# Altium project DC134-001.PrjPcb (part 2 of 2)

## Sheet DC134_USB.SchDoc
size 431 x 279 mm; Date: Not shown in title block; ApprovedBy: Not shown in title block; CheckedBy: Not shown in title block; Author: Not shown in title block; CompanyName: Not shown in title block; Engineer: Not shown in title block; Organization: Not shown in title block; Address1: Not shown in title block; Address2: Not shown in title block; Address3: Not shown in title block; Address4: Not shown in title block; DocumentNumber: 5; Revision: Use project parameter SCH_Rev; SheetNumber: 5; SheetTotal: 9; PageSetup: Record=PageOptions¦CenterHorizontal=True¦CenterVertical=True¦PrintScale=1.00¦XCorrection=1.00¦YCorrection=1.00¦PrintKind=0¦BorderSize=5000000¦LeftOffset=0¦BottomOffset=0¦Orientation=2¦PaperLength=1000¦PaperWidth=1000¦Scale=100¦PaperSource=15¦PrintQuality=600¦MediaType=1¦DitherType=10¦PaperKind=Letter¦PrintScaleMode=1

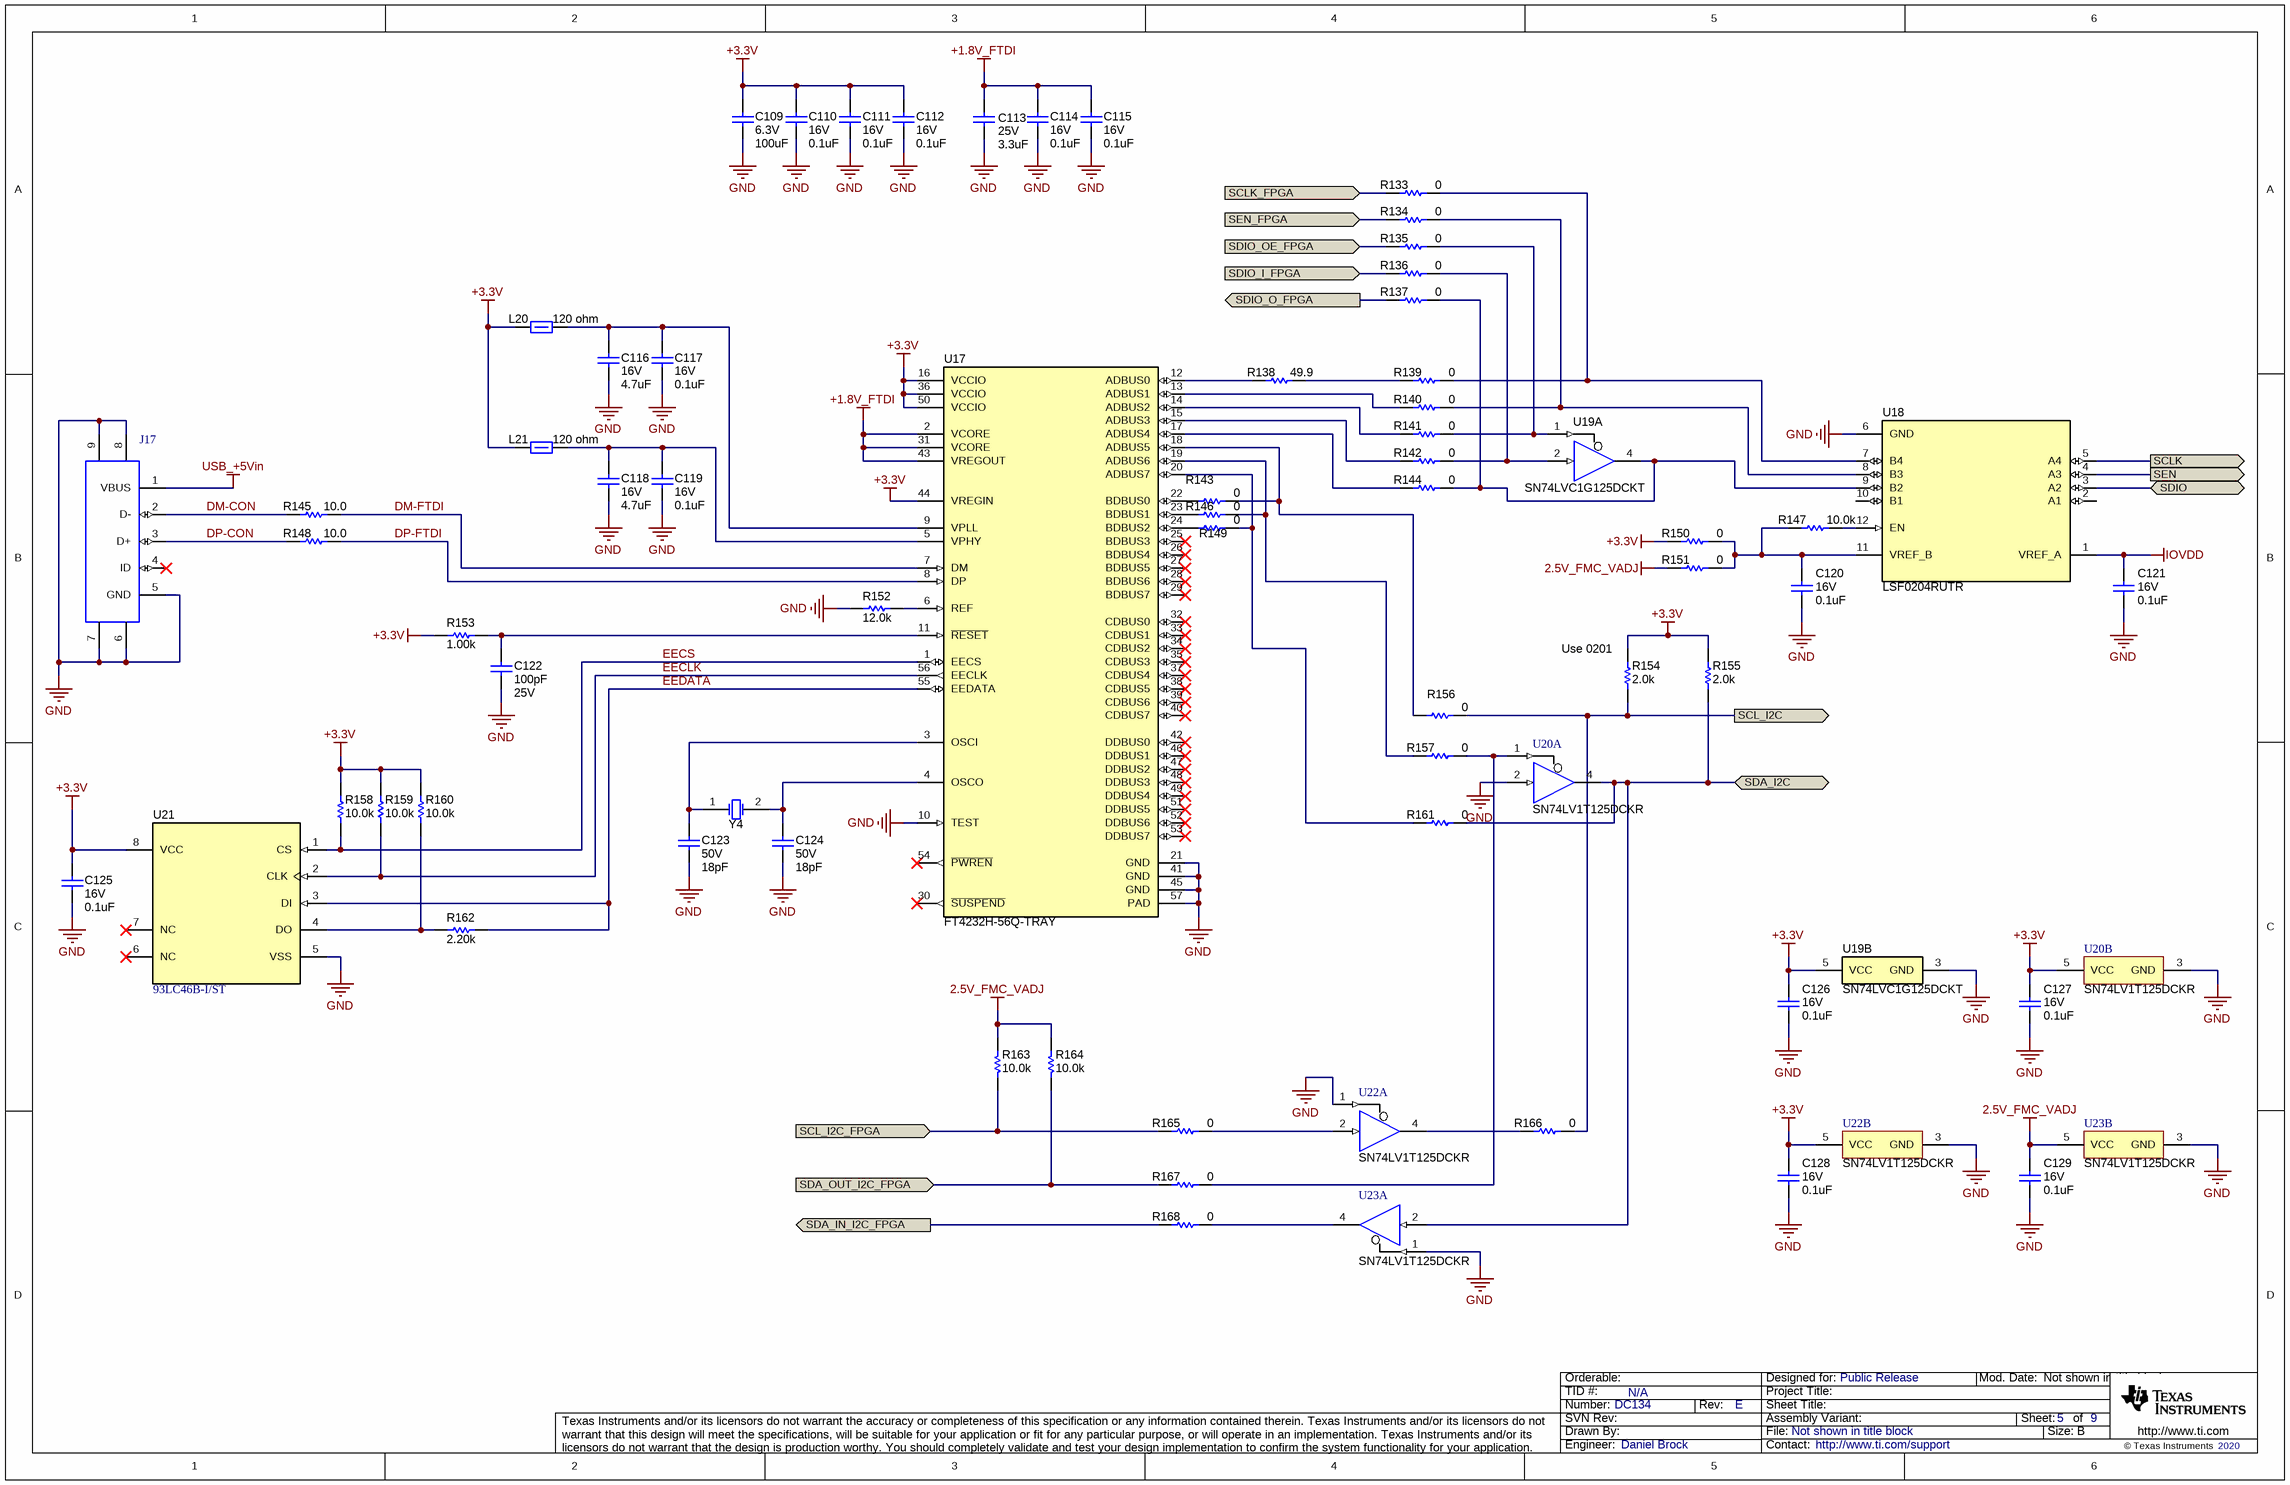
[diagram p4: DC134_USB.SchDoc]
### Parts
C109  VDC_V: 6.3V  ValueDisplayed: 100uF  [1206_190]  (hidden comment: C3216X5R0J107M160AB)
C110  VDC_V: 16V  ValueDisplayed: 0.1uF  [0201L]  (hidden comment: GRM033Z71C104KE14D)
C111  VDC_V: 16V  ValueDisplayed: 0.1uF  [0201L]  (hidden comment: GRM033Z71C104KE14D)
C112  VDC_V: 16V  ValueDisplayed: 0.1uF  [0201L]  (hidden comment: GRM033Z71C104KE14D)
C113  Value2: 25V  ValueDisplayed: 3.3uF  [0603]  (hidden comment: C1608X5R1E335K080AC)
C114  VDC_V: 16V  ValueDisplayed: 0.1uF  [0201L]  (hidden comment: GRM033Z71C104KE14D)
C115  VDC_V: 16V  ValueDisplayed: 0.1uF  [0201L]  (hidden comment: GRM033Z71C104KE14D)
C116  VDC_V: 16V  ValueDisplayed: 4.7uF  [0603]  (hidden comment: GRM188Z71C475KE21D)
C117  VDC_V: 16V  ValueDisplayed: 0.1uF  [0201L]  (hidden comment: GRM033Z71C104KE14D)
C118  VDC_V: 16V  ValueDisplayed: 4.7uF  [0603]  (hidden comment: GRM188Z71C475KE21D)
C119  VDC_V: 16V  ValueDisplayed: 0.1uF  [0201L]  (hidden comment: GRM033Z71C104KE14D)
C120  VDC_V: 16V  ValueDisplayed: 0.1uF  [0201L]  (hidden comment: GRM033Z71C104KE14D)
C121  VDC_V: 16V  ValueDisplayed: 0.1uF  [0201L]  (hidden comment: GRM033Z71C104KE14D)
C122  ValueDisplayed: 100pF  VDC_V: 25V  [0201L]  (hidden comment: CC0201JRNPO8BN101)
C123  VDC_V: 50V  ValueDisplayed: 18pF  [0402L]  (hidden comment: C1005C0G1H180J050BA)
C124  VDC_V: 50V  ValueDisplayed: 18pF  [0402L]  (hidden comment: C1005C0G1H180J050BA)
C125  VDC_V: 16V  ValueDisplayed: 0.1uF  [0201L]  (hidden comment: GRM033Z71C104KE14D)
C126  VDC_V: 16V  ValueDisplayed: 0.1uF  [0201L]  (hidden comment: GRM033Z71C104KE14D)
C127  VDC_V: 16V  ValueDisplayed: 0.1uF  [0201L]  (hidden comment: GRM033Z71C104KE14D)
C128  VDC_V: 16V  ValueDisplayed: 0.1uF  [0201L]  (hidden comment: GRM033Z71C104KE14D)
C129  VDC_V: 16V  ValueDisplayed: 0.1uF  [0201L]  (hidden comment: GRM033Z71C104KE14D)
J17  1734035-2  [CONN_USB-Mini-B-1734035-2]  (value not drawn)
L20  ValueDisplayed: 120 ohm  [0402]  (hidden comment: 74279271)
L21  ValueDisplayed: 120 ohm  [0402]  (hidden comment: 74279271)
R133  ValueDisplayed: 0  [0201L]  (hidden comment: CRCW02010000Z0ED)
R134  ValueDisplayed: 0  [0201L]  (hidden comment: CRCW02010000Z0ED)
R135  ValueDisplayed: 0  [0201L]  (hidden comment: CRCW02010000Z0ED)
R136  ValueDisplayed: 0  [0201L]  (hidden comment: CRCW02010000Z0ED)
R137  ValueDisplayed: 0  [0201L]  (hidden comment: CRCW02010000Z0ED)
R138  ValueDisplayed: 49.9  [0201L]  (hidden comment: RC0201FR-7D49R9L)
R139  ValueDisplayed: 0  [0201L]  (hidden comment: CRCW02010000Z0ED)
R140  ValueDisplayed: 0  [0201L]  (hidden comment: CRCW02010000Z0ED)
R141  ValueDisplayed: 0  [0201L]  (hidden comment: CRCW02010000Z0ED)
R142  ValueDisplayed: 0  [0201L]  (hidden comment: CRCW02010000Z0ED)
R143  ValueDisplayed: 0  [0201L]  (hidden comment: CRCW02010000Z0ED)
R144  ValueDisplayed: 0  [0201L]  (hidden comment: CRCW02010000Z0ED)
R145  ValueDisplayed: 10.0  [0402]  (hidden comment: RK73H1ETTP10R0F)
R146  ValueDisplayed: 0  [0201L]  (hidden comment: CRCW02010000Z0ED)
R147  ValueDisplayed: 10.0k  [0201L]  (hidden comment: RC0201FS-7D10KL)
R148  ValueDisplayed: 10.0  [0402]  (hidden comment: RK73H1ETTP10R0F)
R149  ValueDisplayed: 0  [0201L]  (hidden comment: CRCW02010000Z0ED)
R150  ValueDisplayed: 0  [0201L]  (hidden comment: CRCW02010000Z0ED)
R151  ValueDisplayed: 0  [0201L]  (hidden comment: CRCW02010000Z0ED)
R152  ValueDisplayed: 12.0k  [0201L]  (hidden comment: RC0201FR-7D12KL)
R153  ValueDisplayed: 1.00k  [0201L]  (hidden comment: RC0201FS-7D1KL)
R154  ValueDisplayed: 2.0k  [0402]  (hidden comment: CRCW04022K00JNED)
R155  ValueDisplayed: 2.0k  [0402]  (hidden comment: CRCW04022K00JNED)
R156  ValueDisplayed: 0  [0201L]  (hidden comment: CRCW02010000Z0ED)
R157  ValueDisplayed: 0  [0201L]  (hidden comment: CRCW02010000Z0ED)
R158  ValueDisplayed: 10.0k  [0201L]  (hidden comment: RC0201FR-7D10KL)
R159  ValueDisplayed: 10.0k  [0201L]  (hidden comment: RC0201FR-7D10KL)
R160  ValueDisplayed: 10.0k  [0201L]  (hidden comment: RC0201FR-7D10KL)
R161  ValueDisplayed: 0  [0201L]  (hidden comment: CRCW02010000Z0ED)
R162  ValueDisplayed: 2.20k  [0201L]  (hidden comment: RC0201FR-7D2K2L)
R163  ValueDisplayed: 10.0k  [0201L]  (hidden comment: RC0201FR-7D10KL)
R164  ValueDisplayed: 10.0k  [0201L]  (hidden comment: RC0201FR-7D10KL)
R165  ValueDisplayed: 0  [0201L]  (hidden comment: CRCW02010000Z0ED)
R166  ValueDisplayed: 0  [0201L]  (hidden comment: CRCW02010000Z0ED)
R167  ValueDisplayed: 0  [0201L]  (hidden comment: CRCW02010000Z0ED)
R168  ValueDisplayed: 0  [0201L]  (hidden comment: CRCW02010000Z0ED)
U17  FT4232H-56Q-TRAY  [VQFN-56]
U18  LSF0204RUTR  [RUT0012A]
U19  SN74LVC1G125DCKT  [DCK0005A_N]  (parts A,B of 2)
U20  SN74LV1T125DCKR  [DCK0005A_N]  (parts A,B of 2)
U21  93LC46B-I/ST  [TSSOP-8]
U22  SN74LV1T125DCKR  [DCK0005A_N]  (parts A,B of 2)
U23  SN74LV1T125DCKR  [DCK0005A_N]  (parts A,B of 2)
Y4  ABM3-12.000MHZ-D2Y-T  [XTAL_ABM3]  (value not drawn)

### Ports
SCL_I2C (out), SCL_I2C_FPGA (in), SCLK (out), SCLK_FPGA (in), SDA_I2C (bidir), SDA_IN_I2C_FPGA (out), SDA_OUT_I2C_FPGA (in), SDIO (bidir), SDIO_I_FPGA (in), SDIO_O_FPGA (out), SDIO_OE_FPGA (in), SEN (out), SEN_FPGA (in)

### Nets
2.5V_FMC_VADJ: C129.1 R151.1 R163.1 R164.1 U23.5(VCC)
+1.8V_FTDI: C113.1 C114.2 C115.2 U17.2(VCORE) U17.31(VCORE) U17.43(VREGOUT)
+3.3V: C109.1 C110.2 C111.2 C112.2 C125.2 C126.1 C127.1 C128.1 L20.1 L21.1 R150.1 R153.1 R154.2 R155.2 R158.2 R159.2 R160.2 U17.16(VCCIO) U17.36(VCCIO) U17.44(VREGIN) U17.50(VCCIO) U19.5(VCC) U20.5(VCC) U21.8(VCC) U22.5(VCC)
GND: C109.2 C110.1 C111.1 C112.1 C113.2 C114.1 C115.1 C116.2 C117.1 C118.2 C119.1 C120.2 C121.2 C122.2 C123.2 C124.2 C125.1 C126.2 C127.2 C128.2 C129.2 J17.5(GND) J17.6 J17.7 J17.8 J17.9 R152.1 U17.10(TEST) U17.21(GND) U17.41(GND) U17.45(GND) U17.57(PAD) U18.6(GND) U19.3(GND) U20.2(A) U20.3(GND) U21.5(VSS) U22.1(~{OE}) U22.3(GND) U23.1(~{OE}) U23.3(GND)
IOVDD: C121.1 U18.1(VREF_A)
USB_+5Vin: J17.1(VBUS)
DM-CON: J17.2(D-) R145.1
DM-FTDI: R145.2 U17.7(DM)
DP-CON: J17.3(D+) R148.1
DP-FTDI: R148.2 U17.8(DP)
EECLK: R159.1 U17.56(EECLK) U21.2(CLK)
EECS: R158.1 U17.1(EECS) U21.1(CS)
EEDATA: R162.2 U17.55(EEDATA) U21.3(DI)
SCL_I2C: R154.1 R156.2 R166.2 ; port SCL_I2C
SCL_I2C_FPGA: R163.2 R165.1 ; port SCL_I2C_FPGA
SCLK: U18.5(A4) ; port SCLK
SCLK_FPGA: R133.1 ; port SCLK_FPGA
SDA_I2C: R155.1 R161.2 U20.4(Y) U23.2(A) ; port SDA_I2C
SDA_IN_I2C_FPGA: R168.1 ; port SDA_IN_I2C_FPGA
SDA_OUT_I2C_FPGA: R164.2 R167.1 ; port SDA_OUT_I2C_FPGA
SDIO: U18.3(A2) ; port SDIO
SDIO_I_FPGA: R136.1 ; port SDIO_I_FPGA
SDIO_O_FPGA: R137.1 ; port SDIO_O_FPGA
SDIO_OE_FPGA: R135.1 ; port SDIO_OE_FPGA
SEN: U18.4(A3) ; port SEN
SEN_FPGA: R134.1 ; port SEN_FPGA
NetC116_1: C116.1 C117.2 L20.2 U17.9(VPLL)
NetC118_1: C118.1 C119.2 L21.2 U17.5(VPHY)
NetC120_1: C120.1 R147.2 R150.2 R151.2 U18.11(VREF_B)
NetC122_1: C122.1 R153.2 U17.11(~{RESET})
NetC123_1: C123.1 U17.3(OSCI) Y4.1(OSC1)
NetC124_1: C124.1 U17.4(OSCO) Y4.2(OSC2)
NetR133_2: R133.2 R139.2 U18.7(B4)
NetR134_2: R134.2 R140.2 U18.8(B3)
NetR135_2: R135.2 R141.2 U19.1(~{OE})
NetR136_2: R136.2 R142.2 U19.2(A)
NetR137_2: R137.2 R144.2 U18.9(B2) U19.4(Y)
NetR138_1: R138.1 U17.12(ADBUS0)
NetR138_2: R138.2 R139.1
NetR140_1: R140.1 U17.13(ADBUS1)
NetR141_1: R141.1 U17.14(ADBUS2)
NetR142_1: R142.1 U17.15(ADBUS3)
NetR143_1: R143.1 U17.22(BDBUS0)
NetR143_2: R143.2 R156.1 U17.18(ADBUS5)
NetR144_1: R144.1 U17.17(ADBUS4)
NetR146_1: R146.1 U17.23(BDBUS1)
NetR146_2: R146.2 R157.1 U17.19(ADBUS6)
NetR147_1: R147.1 U18.12(EN)
NetR149_1: R149.1 U17.24(BDBUS2)
NetR149_2: R149.2 R161.1 U17.20(ADBUS7)
NetR152_2: R152.2 U17.6(REF)
NetR157_2: R157.2 R167.2 U20.1(~{OE})
NetR160_1: R160.1 R162.1 U21.4(DO)
NetR165_2: R165.2 U22.2(A)
NetR166_1: R166.1 U22.4(Y)
NetR168_2: R168.2 U23.4(Y)

Not connected (* = marked no-connect by the designer): J17 4(ID)*; U17 25(BDBUS3)* 26(BDBUS4)* 27(BDBUS5)* 28(BDBUS6)* 29(BDBUS7)* 30(~{SUSPEND})* 32(CDBUS0)* 33(CDBUS1)* 34(CDBUS2)* 35(CDBUS3)* 37(CDBUS4)* 38(CDBUS5)* 39(CDBUS6)* 40(CDBUS7)* 42(DDBUS0)* 46(DDBUS1)* 47(DDBUS2)* 48(DDBUS3)* 49(DDBUS4)* 51(DDBUS5)* 52(DDBUS6)* 53(DDBUS7)* 54(~{PWREN})*; U18 2(A1) 10(B1); U21 6(NC)* 7(NC)*

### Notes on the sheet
- (near R154) Use 0201

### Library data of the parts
C109 = CMP-0064957-2: CAP, CERM, 100 uF, 6.3 V,+/- 20%, X5R, 1206; Manufacturer: TDK; TaMin_C: -55°C; Polarized: N; SizeAreaWB_mm2: 10.92; Value1: Unknown; U/M: EA; Value: 100uF; TaMax_C: 85°C; SizeZ_mm: 1.9; SizeX_mm: 3.2; SizeY_mm: 1.6; Cap_Case: 1206; SizeArea_mm2: 5.12; Cap_F: 100µF; AEC Category: Q200
C110-C112 C114 C115 C117 C119 C125 = CMP-0064970-1: CAP, CERM, 0.1 uF, 16 V,+/- 10%, X7R, 0201; Manufacturer: MuRata; TaMin_C: -55°C; Polarized: N; SizeAreaWB_mm2: 2.08; Value1: Unknown; U/M: EA; Value: 0.1uF; TaMax_C: 125°C; SizeZ_mm: 0.26; SizeX_mm: 0.6; SizeY_mm: 0.3; Cap_Case: 0201; SizeArea_mm2: 0.18; Cap_F: 100nF; AEC Category: Q200
C113 = CMP-0007008-5: CAP, CERM, 3.3 uF, 25 V, +/- 10%, X5R, 0603; Manufacturer: TDK; TaMin_C: -55°C; Polarized: N; SizeAreaWB_mm2: 4.68; Value1: Unknown; U/M: EA; Value: 3.3uF; TaMax_C: 85°C; SizeZ_mm: 1; SizeX_mm: 1.6; SizeY_mm: 0.8; SizeArea_mm2: 1.28; Cap_F: 3.3µF; AEC Category: Q200
C116 C118 = CMP-0064936-4: CAP, CERM, 4.7 uF, 16 V,+/- 10%, X7R, 0603; Manufacturer: MuRata; TaMin_C: -55°C; Polarized: N; SizeAreaWB_mm2: 4.68; Value1: Unknown; U/M: EA; Value: 4.7uF; TaMax_C: 125°C; SizeZ_mm: 1; SizeX_mm: 1.6; SizeY_mm: 0.8; SizeArea_mm2: 1.28; Cap_F: 4.7µF; AEC Category: Q200
C120 C121 C126-C129 = CMP-0064970-1: CAP, CERM, 0.1 uF, 16 V,+/- 10%, X7R, 0201; Manufacturer: MuRata; TaMin_C: -55°C; Polarized: N; SizeAreaWB_mm2: 2.08; Value1: Unknown; U/M: EA; Value: 0.1uF; TaMax_C: 125°C; SizeZ_mm: 0.26; SizeX_mm: 0.6; SizeY_mm: 0.3; Cap_Case: 0201; SizeArea_mm2: 0.18; CompType: Capacitor; Cap_F: 100nF; AEC Category: Q200
C122 = CMP-0085847-1: CAP, CERM, 100 pF, 25 V,+/- 5%, C0G/NP0, 0201; Manufacturer: Yageo; Polarized: N; Cap_Case: 0201; SizeX_mm: 0.6; TaMin_C: -55°C; AEC Category: Q200; SizeY_mm: 0.3; SizeZ_mm: 0.26; Value: 100pF; U/M: EA; SizeAreaWB_mm2: 2.08; TaMax_C: 125°C; SizeArea_mm2: 0.18
C123 C124 = CMP-0006247-2: CAP, CERM, 18 pF, 50 V, +/- 5%, C0G/NP0, 0402; Manufacturer: TDK; TaMin_C: -55°C; Polarized: N; SizeAreaWB_mm2: 3; Value1: Unknown; U/M: EA; Value: 18pF; TaMax_C: 125°C; SizeZ_mm: 0.6; SizeX_mm: 1; SizeY_mm: 0.5; Cap_Case: 0402; AEC Category: Q200
J17 = CMP-0054920-3: Connector, Receptacle, Mini-USB Type B, R/A, Top Mount SMT; Manufacturer: TE Connectivity; Green_Lifecycle: Active; Gender: Female; Green_REACh: Incomplete; CompType: USB
L20 L21 = CMP-0003214-1: Ferrite Bead, 120 ohm @ 100 MHz, 0.5 A, 0402; Manufacturer: Wurth Elektronik; Ztyp@1GHz_Ohm: 175.42; ZTyp@100MHz_Ohm: 120; SizeAreaWB_mm2: 3; DCR_ohm: 2d; Value1: 0.2 ohm; Value: 120 ohm; Imax_A: 5dA; SizeZ_mm: 0.6; SizeX_mm: 1; SizeY_mm: 0.5; Value2: 0.5A
R133-R137 R139-R144 R146 R149-R151 R156 R157 R161 R165-R168 = CMP-0027008-4: RES, 0, 5%, 0.05 W, 0201; Manufacturer: Vishay-Dale; Power_W: 50mW; TempCo: ppm/C; Value_Code: 0000; Value: 0; EIA_Code: E24; SizeX_mm: 0.6; SizeY_mm: 0.3; SizeZ_mm: 0.26; Value2: 0.05W; SizeArea_mm2: 0.18; CompType: Resistor; AEC Qualified: N; AEC Category: Q200
R138 = CMP-0028028-1: RES, 49.9, 1%, 0.05 W, 0201; Manufacturer: Yageo America; Power_W: 50mW; TempCo: 200 ppm/C; Value_Code: 49R9; U/M: EA; Value: 49.9; EIA_Code: E96; SizeX_mm: 0.6; SizeY_mm: 0.3; SizeZ_mm: 0.26; Value2: 0.05W; SizeArea_mm2: 0.18; AEC Qualified: N; VDC_V: 25V; AEC Category: Q200
R145 R148 = CMP-0026749-1: RES, 10.0, 1%, 0.063 W, 0402; Manufacturer: KOA Speer; Power_W: 63mW; TempCo: 100 ppm/C; Value_Code: 10R0; U/M: EA; Value: 10.0; EIA_Code: E96; Res_ohm: 10; SizeX_mm: 1; SizeY_mm: 0.5; SizeZ_mm: 0.6; Value2: 0.063W; AEC Qualified: N; VDC_V: 50V; AEC Category: Q200
R147 = CMP-0028071-1: RES, 10.0 k, 1%, 0.05 W, 0201; Manufacturer: Yageo America; Power_W: 50mW; TempCo: 200 ppm/C; Value_Code: 10k0; U/M: EA; Value: 10.0k; EIA_Code: E96; Res_ohm: 10k; SizeX_mm: 0.6; SizeY_mm: 0.3; SizeZ_mm: 0.26; Value2: 0.05W; SizeArea_mm2: 0.18; CompType: Resistor; AEC Qualified: N; VDC_V: 25V; AEC Category: Q200
R152 = CMP-0027954-1: RES, 12.0 k, 1%, 0.05 W, 0201; Manufacturer: Yageo America; Power_W: 50mW; TempCo: 200 ppm/C; Value_Code: 12k0; U/M: EA; Value: 12.0k; Res_ohm: 12k; SizeX_mm: 0.6; SizeY_mm: 0.3; SizeZ_mm: 0.26; Value2: 0.05W; SizeArea_mm2: 0.18; CompType: Resistor; AEC Qualified: N; VDC_V: 25V; AEC Category: Q200
R153 = CMP-0028084-1: RES, 1.00 k, 1%, 0.05 W, 0201; Manufacturer: Yageo America; Power_W: 50mW; TempCo: 200 ppm/C; Value_Code: 1k00; U/M: EA; Value: 1.00k; EIA_Code: E96; Res_ohm: 1k; SizeX_mm: 0.6; SizeY_mm: 0.3; SizeZ_mm: 0.26; Value2: 0.05W; SizeArea_mm2: 0.18; AEC Qualified: N; VDC_V: 25V; AEC Category: Q200
R154 R155 = CMP-0026889-5: RES, 2.0 k, 5%, 0.063 W, AEC-Q200 Grade 0, 0402; Manufacturer: Vishay-Dale; Power_W: 63mW; TempCo: 200 ppm/C; Value_Code: 2k00; Value: 2.0k; EIA_Code: E24; Res_ohm: 2k; SizeX_mm: 1; SizeY_mm: 0.5; SizeZ_mm: 0.6; Value2: 0.063W; AEC Qualified: Y; VDC_V: 50V; AEC Category: Q200; AEC Grade: 0
R158-R160 R163 = CMP-0027945-1: RES, 10.0 k, 1%, 0.05 W, 0201; Manufacturer: Yageo America; Power_W: 50mW; TempCo: 200 ppm/C; Value_Code: 10k0; U/M: EA; Value: 10.0k; EIA_Code: E96; Res_ohm: 10k; SizeX_mm: 0.6; SizeY_mm: 0.3; SizeZ_mm: 0.26; Value2: 0.05W; SizeArea_mm2: 0.18; AEC Qualified: N; VDC_V: 25V; AEC Category: Q200
R162 = CMP-0027995-1: RES, 2.20 k, 1%, 0.05 W, 0201; Manufacturer: Yageo America; Power_W: 50mW; TempCo: 200 ppm/C; Value_Code: 2k20; U/M: EA; Value: 2.20k; Res_ohm: 2.2k; SizeX_mm: 0.6; SizeY_mm: 0.3; SizeZ_mm: 0.26; Value2: 0.05W; SizeArea_mm2: 0.18; AEC Qualified: N; VDC_V: 25V; AEC Category: Q200
R164 = CMP-0027945-1: RES, 10.0 k, 1%, 0.05 W, 0201; Manufacturer: Yageo America; Power_W: 50mW; TempCo: 200 ppm/C; Value_Code: 10k0; U/M: EA; Value: 10.0k; EIA_Code: E96; Res_ohm: 10k; SizeX_mm: 0.6; SizeY_mm: 0.3; SizeZ_mm: 0.26; Value2: 0.05W; SizeArea_mm2: 0.18; CompType: Resistor; AEC Qualified: N; VDC_V: 25V; AEC Category: Q200
U17 = CMP-0081661-1: Future Technology Devices International Ltd FT4232H Quad High Speed USB to Multipurpose UART/MPSSE IC, VQFN-56; Manufacturer: FTDI; SizeZ_mm: 1; SizeX_mm: 8; SizeArea_mm2: 64; SizeAreaWB_mm2: 100
U18 = CMP-0066443-2: 4-Bit Bidirectional Multi-Voltage Level Translator for Open-Drain & Push- Pull, RUT0012A (UQFN-12); Manufacturer: Texas Instruments; SizeZ_mm: 0.55; SizeX_mm: 1.7; SizeY_mm: 2.0; SizeArea_mm2: 3.4; CompType: IC; U/M: EA; SizeAreaWB_mm2: 8.1
U19 = CMP-0051305-3: Single Bus Buffer Gate With 3-State Outputs, DCK0005A, SMALL T&R; Manufacturer: Texas Instruments; Output Type: CMOS; tpd @ Nom Voltage(Max)(ns): 9,5.5,4.5,4; VCC(Max)(V): 5.5; 3-State Output: Yes; VCC(Min)(V): 1.65; Input Type: CMOS/TTL; Rating: Catalog; Sub-Family: Non-Inverting Buffer/Driver; F @ Nom Voltage(Max)(Mhz): 150; Bits(#): 1; Schmitt Trigger: No; Voltage(Nom)(V): 1.8,2.5,3.3,5; Output Drive (IOL/IOH)(Max)(mA): 32/-32; Technology Family: LVC; ICC @ Nom Voltage(Max)(mA): 0.01; Logic: True; AEC Category: Q200; AEC Qualified: N; CompType: IC; SizeAreaWB_mm2: 9.3; SizeArea_mm2: 4.2; SizeX_mm: 2.1; SizeY_mm: 2.0; SizeZ_mm: 1.1
U20 U22 U23 = CMP-0051325-2: Single Power Supply, Single BUFFER GATE w/ 3-State Output (active low enable), DCK0005A, LARGE T&R; Manufacturer: Texas Instruments; tpd @ Nom Voltage(Max)(ns): 14.5,9.5,8.0,6.5; Output Drive (IOL/IOH)(Max)(mA): 8/-8; Voltage(Nom)(V): 1.8,2.5,3.3,5.5; Bits(#): 1; Rating: Catalog; Output Type: CMOS; Technology Family: LV1T; 3-State Output: Yes; Sub-Family: Non-Inverting Buffer/Driver; Logic: True; Input Type: TTL; Schmitt Trigger: No; VCC(Min)(V): 1.6; Special Features: 1.8V to 3.3V Up Translation,3.3V to 1.8V Down Translation,5V Input Tolerant; VCC(Max)(V): 5.5; ICC @ Nom Voltage(Max)(mA): 0.01; F @ Nom Voltage(Max)(Mhz): 50; AEC Category: Q200; AEC Qualified: N; CompType: IC; SizeAreaWB_mm2: 9.3; SizeArea_mm2: 4.2; SizeX_mm: 2.1; SizeY_mm: 2.0; SizeZ_mm: 1.1
U21 = CMP-0081524-1: 1K Microwire Compatible Serial EEPROM, TSSOP-8; Manufacturer: Microchip; SizeArea_mm2: 19.2; SizeAreaWB_mm2: 42; SizeY_mm: 3; SizeZ_mm: 1.2; SizeX_mm: 6.4
Y4 = CMP-0004616-3: Crystal, 12 MHz, 18 pF, SMD; Manufacturer: Abracon Corporation; TaMin_C: -40°C; Frequency Stability: +/-30ppm; Frequency_Fixed: 12MHz; TaMax_C: 85°C

## Sheet DC134_Power.SchDoc: Power-Supply_Buffer
size 431 x 279 mm; Date: Not shown in title block; ApprovedBy: Not shown in title block; CheckedBy: Not shown in title block; Author: Not shown in title block; CompanyName: Not shown in title block; DrawnBy: Daniel Brock; Engineer: Not shown in title block; Organization: Not shown in title block; Address1: Not shown in title block; Address2: Not shown in title block; Address3: Not shown in title block; Address4: Not shown in title block; DocumentNumber: 6; Revision: Use project parameter SCH_Rev; SheetNumber: 6; SheetTotal: 9; PageSetup: Record=PageOptions¦CenterHorizontal=True¦CenterVertical=True¦PrintScale=1.00¦XCorrection=1.00¦YCorrection=1.00¦PrintKind=0¦BorderSize=5000000¦LeftOffset=0¦BottomOffset=0¦Orientation=2¦PaperLength=1000¦PaperWidth=1000¦Scale=100¦PaperSource=15¦PrintQuality=600¦MediaType=1¦DitherType=10¦PaperKind=Letter¦PrintScaleMode=1

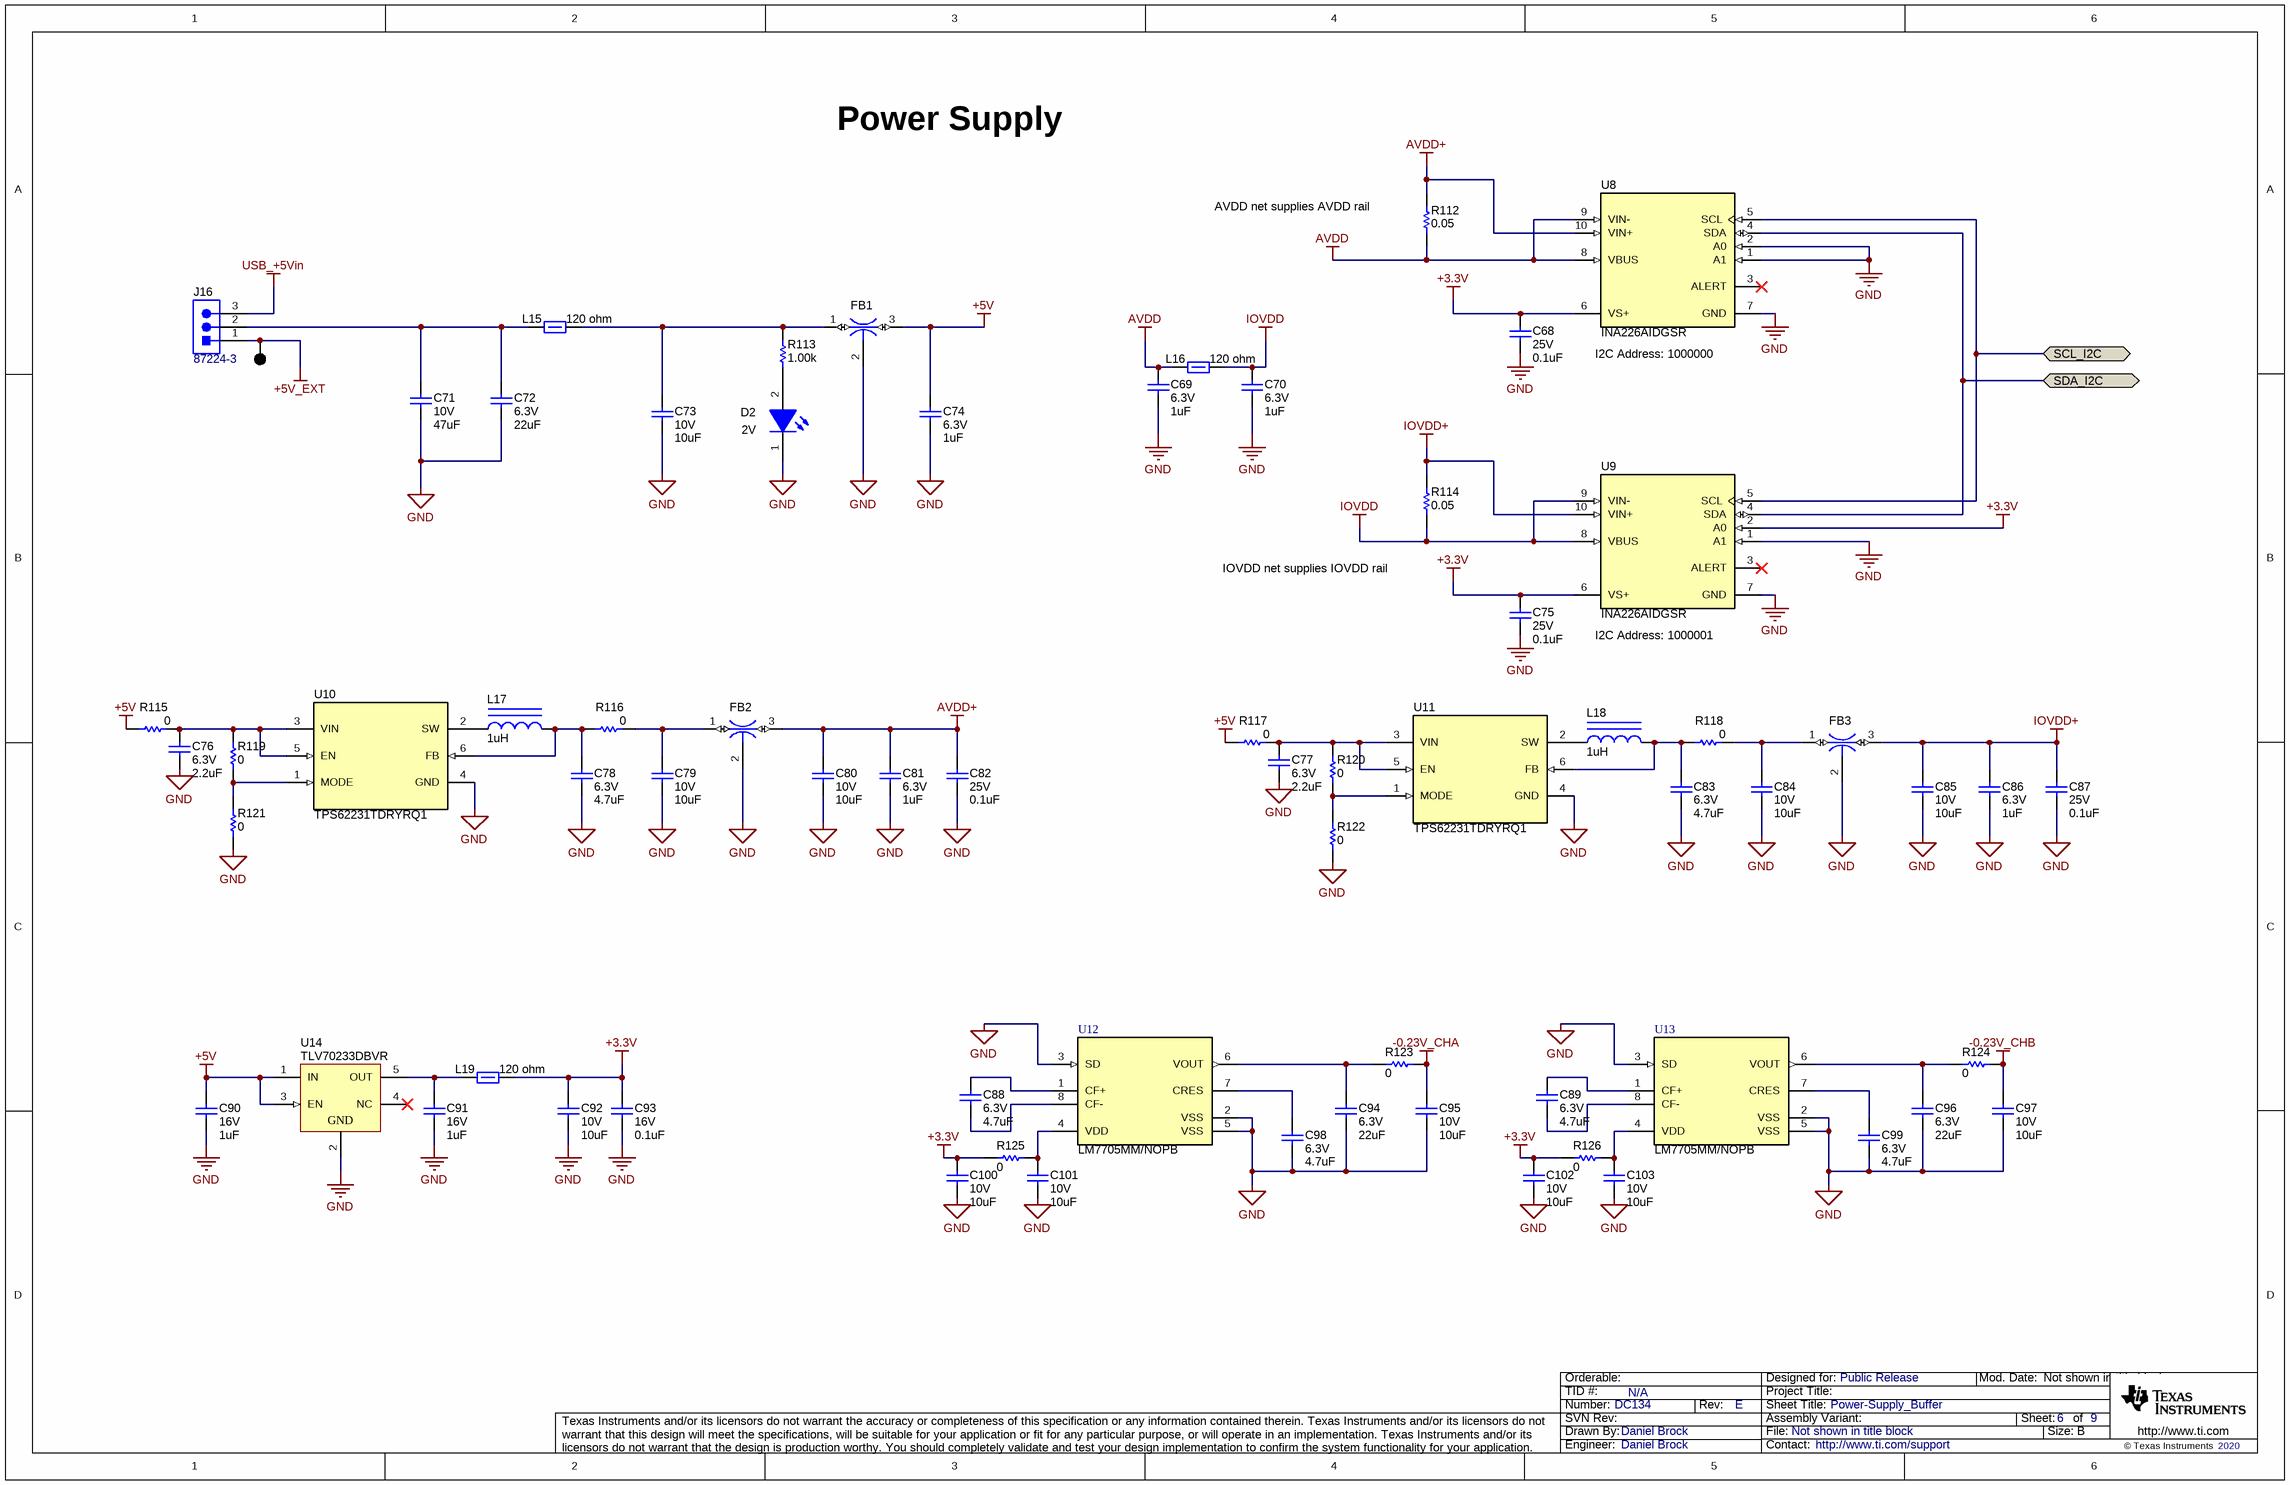
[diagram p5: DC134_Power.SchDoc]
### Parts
+1  5011  [Keystone5011]  (value not drawn)
C68  VDC_V: 25V  ValueDisplayed: 0.1uF  [0402]  (hidden comment: GRM155R61E104KA87D)
C69  VDC_V: 6.3V  ValueDisplayed: 1uF  [0402]  (hidden comment: GRM152R60J105ME15D)
C70  VDC_V: 6.3V  ValueDisplayed: 1uF  [0402]  (hidden comment: GRM152R60J105ME15D)
C71  VDC_V: 10V  ValueDisplayed: 47uF  [1210_270]  (hidden comment: GRM32ER61A476KE20L)
C72  VDC_V: 6.3V  ValueDisplayed: 22uF  [0805_HV]  (hidden comment: JMK212BJ226MG-T)
C73  VDC_V: 10V  ValueDisplayed: 10uF  [0603]  (hidden comment: GRM188R61A106ME69D)
C74  VDC_V: 6.3V  ValueDisplayed: 1uF  [0402]  (hidden comment: GRM152R60J105ME15D)
C75  VDC_V: 25V  ValueDisplayed: 0.1uF  [0402]  (hidden comment: GRM155R61E104KA87D)
C76  VDC_V: 6.3V  ValueDisplayed: 2.2uF  [0402]  (hidden comment: GRM155R60J225ME15D)
C77  VDC_V: 6.3V  ValueDisplayed: 2.2uF  [0402]  (hidden comment: GRM155R60J225ME15D)
C78  VDC_V: 6.3V  ValueDisplayed: 4.7uF  [0603]  (hidden comment: C0603C475K9PACTU)
C79  VDC_V: 10V  ValueDisplayed: 10uF  [0603]  (hidden comment: GRM188R61A106ME69D)
C80  VDC_V: 10V  ValueDisplayed: 10uF  [0603]  (hidden comment: GRM188R61A106ME69D)
C81  VDC_V: 6.3V  ValueDisplayed: 1uF  [0402]  (hidden comment: GRM152R60J105ME15D)
C82  VDC_V: 25V  ValueDisplayed: 0.1uF  [0201_033]  (hidden comment: GRM033R61E104KE14J)
C83  VDC_V: 6.3V  ValueDisplayed: 4.7uF  [0603]  (hidden comment: C0603C475K9PACTU)
C84  VDC_V: 10V  ValueDisplayed: 10uF  [0603]  (hidden comment: GRM188R61A106ME69D)
C85  VDC_V: 10V  ValueDisplayed: 10uF  [0603]  (hidden comment: GRM188R61A106ME69D)
C86  VDC_V: 6.3V  ValueDisplayed: 1uF  [0402]  (hidden comment: GRM152R60J105ME15D)
C87  VDC_V: 25V  ValueDisplayed: 0.1uF  [0201_033]  (hidden comment: GRM033R61E104KE14J)
C88  VDC_V: 6.3V  ValueDisplayed: 4.7uF  [0603]  (hidden comment: C0603C475K9PACTU)
C89  VDC_V: 6.3V  ValueDisplayed: 4.7uF  [0603]  (hidden comment: C0603C475K9PACTU)
C90  VDC_V: 16V  ValueDisplayed: 1uF  [0603]  (hidden comment: 885012206052)
C91  VDC_V: 16V  ValueDisplayed: 1uF  [0603]  (hidden comment: 885012206052)
C92  VDC_V: 10V  ValueDisplayed: 10uF  [0805_HV]  (hidden comment: 885012207026)
C93  VDC_V: 16V  ValueDisplayed: 0.1uF  [0201L]  (hidden comment: GRM033Z71C104KE14D)
C94  VDC_V: 6.3V  ValueDisplayed: 22uF  [0805_HV]  (hidden comment: JMK212BJ226MG-T)
C95  VDC_V: 10V  ValueDisplayed: 10uF  [0805_HV]  (hidden comment: 885012207026)
C96  VDC_V: 6.3V  ValueDisplayed: 22uF  [0805_HV]  (hidden comment: JMK212BJ226MG-T)
C97  VDC_V: 10V  ValueDisplayed: 10uF  [0805_HV]  (hidden comment: 885012207026)
C98  VDC_V: 6.3V  ValueDisplayed: 4.7uF  [0603]  (hidden comment: C0603C475K9PACTU)
C99  VDC_V: 6.3V  ValueDisplayed: 4.7uF  [0603]  (hidden comment: C0603C475K9PACTU)
C100  VDC_V: 10V  ValueDisplayed: 10uF  [0805_HV]  (hidden comment: 885012207026)
C101  VDC_V: 10V  ValueDisplayed: 10uF  [0805_HV]  (hidden comment: 885012207026)
C102  VDC_V: 10V  ValueDisplayed: 10uF  [0805_HV]  (hidden comment: 885012207026)
C103  VDC_V: 10V  ValueDisplayed: 10uF  [0805_HV]  (hidden comment: 885012207026)
D2  Value2: 2V  [LTST-C150_1206_Green]  (hidden comment: LTST-C150KGKT)
FB1  NFM31PC276B0J3L  [Murata_NFM31P]  (value not drawn)
FB2  NFM31PC276B0J3L  [Murata_NFM31P]  (value not drawn)
FB3  NFM31PC276B0J3L  [Murata_NFM31P]  (value not drawn)
J16  87224-3  [TE_87224-3]
L15  ValueDisplayed: 120 ohm  [0402]  (hidden comment: 74279271)
L16  ValueDisplayed: 120 ohm  [0402]  (hidden comment: 74279271)
L17  ValueDisplayed: 1uH  [0805_HV]  (hidden comment: LQM21PN1R0MC0D)
L18  ValueDisplayed: 1uH  [0805_HV]  (hidden comment: LQM21PN1R0MC0D)
L19  ValueDisplayed: 120 ohm  [0402]  (hidden comment: 74279271)
R112  ValueDisplayed: 0.05  [0603]  (hidden comment: ERJ-L03KF50MV)
R113  ValueDisplayed: 1.00k  [0402]  (hidden comment: RC0402FR-071KL)
R114  ValueDisplayed: 0.05  [0603]  (hidden comment: ERJ-L03KF50MV)
R115  value 0  [0402]  (hidden comment: Resistor)
R116  value 0  [0402]  (hidden comment: Resistor)
R117  value 0  [0402]  (hidden comment: Resistor)
R118  value 0  [0402]  (hidden comment: Resistor)
R119  value 0  [0402]  (hidden comment: Resistor)
R120  value 0  [0402]  (hidden comment: Resistor)
R121  value 0  [0402]  (hidden comment: Resistor)
R122  value 0  [0402]  (hidden comment: Resistor)
R123  ValueDisplayed: 0  [0402]  (hidden comment: RK73Z1ETTP)
R124  ValueDisplayed: 0  [0402]  (hidden comment: RK73Z1ETTP)
R125  ValueDisplayed: 0  [0402]  (hidden comment: RK73Z1ETTP)
R126  ValueDisplayed: 0  [0402]  (hidden comment: RK73Z1ETTP)
U8  INA226AIDGSR  [DGS0010A_L]
U9  INA226AIDGSR  [DGS0010A_L]
U10  TPS62231TDRYRQ1  [DRY0006A]
U11  TPS62231TDRYRQ1  [DRY0006A]
U12  LM7705MM/NOPB  [DGK0008A_N]
U13  LM7705MM/NOPB  [DGK0008A_N]
U14  TLV70233DBVR  [DBV0005A_N]

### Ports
SCL_I2C (bidir), SDA_I2C (bidir)

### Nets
+3.3V: C68.1 C75.1 C92.1 C93.2 C100.1 C102.1 L19.2 R125.1 R126.1 U8.6(VS+) U9.2(A0) U9.6(VS+)
+5V: C74.1 C90.1 FB1.3 R115.1 R117.1 U14.1(IN) U14.3(EN)
+5V_EXT: +1.+5V_EXT J16.1
-0.23V_CHA: C95.1 R123.2
-0.23V_CHB: C97.1 R124.2
AVDD: C69.1 L16.1 R112.1 U8.8(VBUS) U8.9(VIN-)
AVDD+: C80.1 C81.1 C82.1 FB2.3 R112.2 U8.10(VIN+)
GND: C68.2 C69.2 C70.2 C71.2 C72.2 C73.2 C74.2 C75.2 C76.2 C77.2 C78.2 C79.2 C80.2 C81.2 C82.2 C83.2 C84.2 C85.2 C86.2 C87.2 C90.2 C91.2 C92.2 C93.1 C94.2 C95.2 C96.2 C97.2 C98.2 C99.2 C100.2 C101.2 C102.2 C103.2 D2.1(K) FB1.2 FB2.2 FB3.2 R121.1 R122.1 U8.1(A1) U8.2(A0) U8.7(GND) U9.1(A1) U9.7(GND) U10.4(GND) U11.4(GND) U12.2(VSS) U12.3(SD) U12.5(VSS) U13.2(VSS) U13.3(SD) U13.5(VSS) U14.2(GND)
IOVDD: C70.1 L16.2 R114.1 U9.8(VBUS) U9.9(VIN-)
IOVDD+: C85.1 C86.1 C87.1 FB3.3 R114.2 U9.10(VIN+)
USB_+5Vin: J16.3
SCL_I2C: U8.5(SCL) U9.5(SCL) ; port SCL_I2C
SDA_I2C: U8.4(SDA) U9.4(SDA) ; port SDA_I2C
NetC71_1: C71.1 C72.1 J16.2 L15.1
NetC73_1: C73.1 FB1.1 L15.2 R113.2
NetC76_1: C76.1 R115.2 R119.2 U10.3(VIN) U10.5(EN)
NetC77_1: C77.1 R117.2 R120.2 U11.3(VIN) U11.5(EN)
NetC78_1: C78.1 L17.2 R116.1 U10.6(FB)
NetC79_1: C79.1 FB2.1 R116.2
NetC83_1: C83.1 L18.2 R118.1 U11.6(FB)
NetC84_1: C84.1 FB3.1 R118.2
NetC88_1: C88.1 U12.1(CF+)
NetC88_2: C88.2 U12.8(CF-)
NetC89_1: C89.1 U13.1(CF+)
NetC89_2: C89.2 U13.8(CF-)
NetC91_1: C91.1 L19.1 U14.5(OUT)
NetC94_1: C94.1 R123.1 U12.6(VOUT)
NetC96_1: C96.1 R124.1 U13.6(VOUT)
NetC98_1: C98.1 U12.7(CRES)
NetC99_1: C99.1 U13.7(CRES)
NetC101_1: C101.1 R125.2 U12.4(VDD)
NetC103_1: C103.1 R126.2 U13.4(VDD)
NetD2_2: D2.2(A) R113.1
NetL17_1: L17.1 U10.2(SW)
NetL18_1: L18.1 U11.2(SW)
NetR119_1: R119.1 R121.2 U10.1(MODE)
NetR120_1: R120.1 R122.2 U11.1(MODE)

Not connected (* = marked no-connect by the designer): U8 3(ALERT)*; U9 3(ALERT)*; U14 4(NC)*

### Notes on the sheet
- Power Supply
- (near R112) AVDD net supplies AVDD rail
- (near U8) I2C Address: 1000000
- IOVDD net supplies IOVDD rail
- (near U9) I2C Address: 1000001

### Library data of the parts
+1 = CMP-0055148-1: Test Point, Multipurpose, Black, TH; Manufacturer: Keystone; CNHeader: FALSE; Green_Lifecycle: Active; Green_REACh: Passed; ContactFinish: Silver; CT: TRUE
C68 C75 = CMP-0006607-2: CAP, CERM, 0.1 uF, 25 V, +/- 10%, X5R, 0402; Manufacturer: MuRata; TaMin_C: -55°C; Polarized: N; SizeAreaWB_mm2: 3; Value1: Unknown; U/M: EA; Value: 0.1uF; TaMax_C: 85°C; SizeZ_mm: 0.6; SizeX_mm: 1; SizeY_mm: 0.5; Cap_F: 100nF; AEC Category: Q200
C69 C70 C74 C81 C86 = CMP-0006372-2: CAP, CERM, 1 uF, 6.3 V, +/- 20%, X5R, 0402; Manufacturer: MuRata; TaMin_C: -55°C; Polarized: N; SizeAreaWB_mm2: 3; Value1: Unknown; U/M: EA; Value: 1uF; TaMax_C: 85°C; SizeZ_mm: 0.6; SizeX_mm: 1; SizeY_mm: 0.5; Cap_F: 1µF; AEC Category: Q200
C71 = CMP-0009208-2: CAP, CERM, 47 uF, 10 V, +/- 10%, X5R, 1210; Manufacturer: MuRata; TaMin_C: -55°C; ESR_ohm: 1m; Polarized: N; SizeAreaWB_mm2: 14.7; Value1: 0.001 ohm; U/M: EA; Value: 47uF; TaMax_C: 85°C; SizeZ_mm: 2.7; SizeX_mm: 3.2; SizeY_mm: 2.5; Cap_Case: 1210; SizeArea_mm2: 8; Cap_F: 47µF; AEC Category: Q200
C72 C94 C96 = CMP-0008391-2: CAP, CERM, 22 uF, 6.3 V, +/- 20%, X5R, 0805; Manufacturer: Taiyo Yuden; TaMin_C: -55°C; Polarized: N; SizeAreaWB_mm2: 6.75; Value1: Unknown; U/M: EA; Value: 22uF; TaMax_C: 85°C; SizeZ_mm: 1.45; SizeX_mm: 2; SizeY_mm: 1.25; Cap_Case: 0805; SizeArea_mm2: 2.5; Cap_F: 22µF; AEC Category: Q200
C73 C79 C80 C84 C85 = CMP-0007318-5: CAP, CERM, 10 uF, 10 V, +/- 20%, X5R, 0603; Manufacturer: MuRata; TaMin_C: -55°C; Polarized: N; SizeAreaWB_mm2: 4.68; Value1: Unknown; U/M: EA; Value: 10uF; TaMax_C: 85°C; SizeZ_mm: 1; SizeX_mm: 1.6; SizeY_mm: 0.8; SizeArea_mm2: 1.28; Cap_F: 10µF; AEC Category: Q200
C76 C77 = CMP-0006544-2: CAP, CERM, 2.2 uF, 6.3 V, +/- 20%, X5R, 0402; Manufacturer: MuRata; TaMin_C: -55°C; ESR_ohm: 5m; Polarized: N; SizeAreaWB_mm2: 3; Value1: 0.005 ohm; U/M: EA; Value: 2.2uF; TaMax_C: 125°C; SizeZ_mm: 0.6; SizeX_mm: 1; SizeY_mm: 0.5; Cap_F: 2.2µF; IRMS_A: 3.67A; AEC Category: Q200
C78 C83 C88 C89 C98 C99 = CMP-0006950-5: CAP, CERM, 4.7 uF, 6.3 V, +/- 10%, X5R, 0603; Manufacturer: Kemet; TaMin_C: -55°C; ESR_ohm: 6m; Polarized: N; SizeAreaWB_mm2: 4.68; Value1: 0.006 ohm; U/M: EA; Value: 4.7uF; TaMax_C: 85°C; SizeZ_mm: 1; SizeX_mm: 1.6; SizeY_mm: 0.8; SizeArea_mm2: 1.28; Cap_F: 4.7µF; IRMS_A: 7.24A; AEC Category: Q200
C82 C87 = CMP-0009719-2: CAP, CERM, 0.1 uF, 25 V, +/- 10%, X5R, 0201; Manufacturer: MuRata; TaMin_C: -55°C; Polarized: N; SizeAreaWB_mm2: 2.08; Value1: Unknown; U/M: EA; Value: 0.1uF; TaMax_C: 85°C; SizeZ_mm: 0.33; SizeX_mm: 0.6; SizeY_mm: 0.3; Cap_Case: 0201; SizeArea_mm2: 0.18; Cap_F: 100nF; AEC Category: Q200
C90 C91 = CMP-0006831-4: CAP, CERM, 1 uF, 16 V, +/- 10%, X7R, 0603; Manufacturer: Wurth Elektronik; TaMin_C: -55°C; Polarized: N; SizeAreaWB_mm2: 4.68; Value1: Unknown; U/M: EA; Value: 1uF; TaMax_C: 125°C; SizeZ_mm: 1; SizeX_mm: 1.6; SizeY_mm: 0.8; SizeArea_mm2: 1.28; Cap_F: 1µF; AEC Category: Q200
C92 C95 C97 C100-C103 = CMP-0007691-2: CAP, CERM, 10 uF, 10 V, +/- 10%, X7R, 0805; Manufacturer: Wurth Elektronik; TaMin_C: -55°C; Polarized: N; SizeAreaWB_mm2: 6.75; Value1: Unknown; U/M: EA; Value: 10uF; TaMax_C: 125°C; SizeZ_mm: 1.45; SizeX_mm: 2; SizeY_mm: 1.25; Cap_Case: 0805; SizeArea_mm2: 2.5; Cap_F: 10µF; AEC Category: Q200
C93 = CMP-0064970-1: as C110 on sheet DC134_USB
D2 = CMP-0002920-2: LED, Green, SMD; Manufacturer: LiteOn; Io_A: 30mA; Vr_V: 5V; Tjmax_C: 85°C; Value1: W; Angle: 130; Type: AlInGaP
FB1-FB3 = CMP-0001934-2: FILTER LC HIGH FREQ 27uF 1206; Manufacturer: MuRata
J16 = CMP-0078139-1: Header, 2.54mm, 3x1, Gold, TH; Manufacturer: TE Connectivity; Pitch_mm: 2.54; Gender: Male; Cert_UL: Y; Current_A: 3A; Voltage_V: 750V; Green_REACh: Passed; Shrouded: N; Green_Lifecycle: Active; Row_Count: 1
L15 L16 L19 = CMP-0003214-1: as L20 on sheet DC134_USB
L17 L18 = CMP-0058739-1: Inductor, Multilayer, Ferrite, 1 uH, 0.8 A, 0.19 ohm, SMD; Manufacturer: MuRata; Irms: 0.8A @ 40C rise; Green_Lifecycle: Active; SizeAreaWB_mm2: 6.75; DCR_ohm: 0.19; Green_REACh: Passed; Value: 1uH; Imax_A: 800mA; SizeZ_mm: 1.45; SizeX_mm: 2; SizeY_mm: 1.25; Value2: 0.8A; SizeArea_mm2: 2.5; Ind_H: 1µH; AEC Category: Q200
R112 R114 = CMP-0022727-3: RES, 0.05, 1%, 0.1 W, AEC-Q200 Grade 1, 0603; Manufacturer: Panasonic; Power_W: 100mW; TempCo: 200 ppm/C; Value_Code: R050; Value: 0.05; EIA_Code: E96; SizeX_mm: 1.6; SizeY_mm: 0.8; SizeZ_mm: 1; Value2: 0.1W; SizeArea_mm2: 1.28; AEC Qualified: Y; AEC Category: Q200; SizeAreaWB_mm2: 4.68
R113 = CMP-0026725-1: RES, 1.00 k, 1%, 0.0625 W, 0402; Manufacturer: Yageo America; Power_W: 62.5mW; TempCo: 100 ppm/C; Value_Code: 1k00; U/M: EA; Value: 1.00k; EIA_Code: E96; Res_ohm: 1k; SizeX_mm: 1; SizeY_mm: 0.5; SizeZ_mm: 0.6; AEC Qualified: N; VDC_V: 50V; AEC Category: Q200
R115-R122 = CMP-0026822-3: RES, 0, 5%, 0.063 W, AEC-Q200 Grade 0, 0402; Manufacturer: Vishay-Dale; PartNumber: CRCW04020000Z0ED; Value_Code: 0000; Power_W: 63mW; Value2: 0.063W; VDC_V: 50V; TempCo: 200 ppm/C; EIA_Code: E24; AEC Category: Q200; AEC Qualified: Y; SizeArea_mm2: 0.5; SizeX_mm: 1; SizeZ_mm: 0.6
R123-R126 = CMP-0027007-2: RES, 0, 5%, 0.063 W, AEC-Q200 Grade 0, 0402; Manufacturer: KOA Speer; Power_W: 63mW; TempCo: ppm/C; Value_Code: 0000; U/M: EA; Value: 0; EIA_Code: E24; SizeX_mm: 1; SizeY_mm: 0.5; SizeZ_mm: 0.6; Value2: 0.063W; AEC Qualified: Y; AEC Category: Q200
U8 U9 = CMP-0037979-1: High-Side Measurement, Bi-Directional Current / Power Monitor with I2C Interface, 2.7 to 5.5 V, -40 to 125 degC, 10-pin SOP (DGS10), Green (RoHS & no Sb/Br); Common Mode Range(Max)(V): 36; Vs(Min)(V): 2.7; SubFamily: Current Shunt Monitor; Small-Signal Bandwidth(Typ)(MHz): 0.007; CMRR(Min)(dB): 126; Gain(V/V): 1; Vs(Max)(V): 5.5; Rating: Catalog; Input Offset Drift (+/-)(Max)(uV/Degrees Celsius): 0.1; Quiescent Current (+/-)(Typ)(mA): 0.33; Common Mode Range(Min)(V): 0; Input Offset (+/-)(Max)(uV): 10
U10 U11 = CMP-0074035-3: Automotive 2V to 6V, 500mA Buck Converter with 1.8V Fixed Output Voltage in 1x1.5mm SON Package, DRY0006A (USON-6); Manufacturer: Texas Instruments; SizeAreaWB_mm2: 4.9; SizeZ_mm: 0.6; SizeX_mm: 1.0; SizeY_mm: 1.45; CompType: IC; AEC Category: Q200; AEC Qualified: Y
U12 U13 = CMP-0072065-2: Low Noise Negative Bias Generator, 8-pin Mini SOIC, Pb-Free; Manufacturer: Texas Instruments; CompType: IC; PowerWise: N
U14 = CMP-0035516-1: Single Output LDO, 300 mA, Fixed 3.3 V Output, 2 to 5.5 V Input, with Low IQ, 5-pin SOT-23 (DBV), -40 to 125 degC, Green (RoHS & no Sb/Br); Manufacturer: Texas Instruments; Fixed Output Options(V): 3.3; Vdo(Typ)(mV): 220; Accuracy(%): 2; Iq(Typ)(mA): 0.03; SubFamily: Single Channel LDO; Iout(Max)(A): 0.3; Vin(Max)(V): 5.5

## Sheet DC134_Reference.SchDoc
size 431 x 279 mm; Date: Not shown in title block; ApprovedBy: Not shown in title block; CheckedBy: Not shown in title block; Author: Not shown in title block; CompanyName: Not shown in title block; Engineer: Not shown in title block; Organization: Not shown in title block; Address1: Not shown in title block; Address2: Not shown in title block; Address3: Not shown in title block; Address4: Not shown in title block; DocumentNumber: 7; Revision: Use project parameter SCH_Rev; SheetNumber: 7; SheetTotal: 9; PageSetup: Record=PageOptions¦CenterHorizontal=True¦CenterVertical=True¦PrintScale=1.00¦XCorrection=1.00¦YCorrection=1.00¦PrintKind=0¦BorderSize=5000000¦LeftOffset=0¦BottomOffset=0¦Orientation=2¦PaperLength=1000¦PaperWidth=1000¦Scale=100¦PaperSource=15¦PrintQuality=600¦MediaType=1¦DitherType=10¦PaperKind=Letter¦PrintScaleMode=1

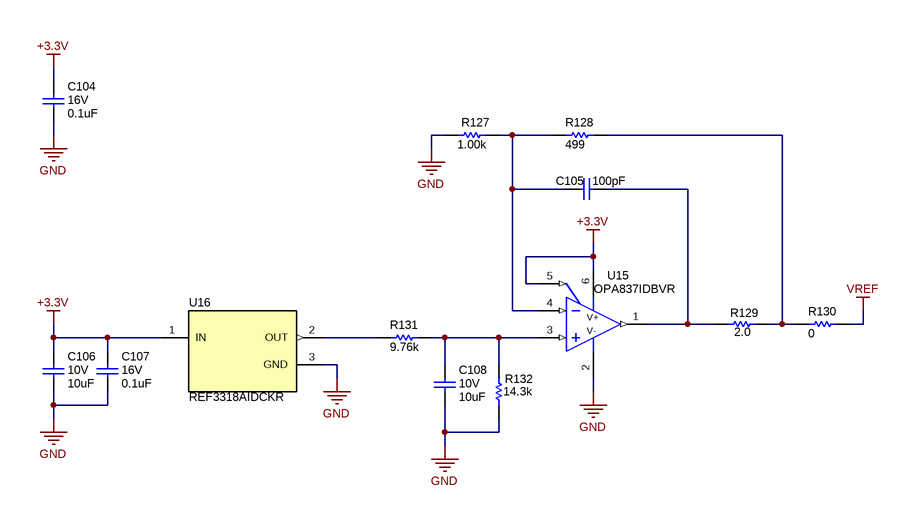
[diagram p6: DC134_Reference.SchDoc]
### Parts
C104  VDC_V: 16V  ValueDisplayed: 0.1uF  [0201L]  (hidden comment: GRM033Z71C104KE14D)
C105  ValueDisplayed: 100pF  [0201_033L]  (hidden comment: GRM033R71E101JA01D)
C106  VDC_V: 10V  ValueDisplayed: 10uF  [0603L]  (hidden comment: GRM188Z71A106MA73D)
C107  VDC_V: 16V  ValueDisplayed: 0.1uF  [0201L]  (hidden comment: GRM033Z71C104KE14D)
C108  VDC_V: 10V  ValueDisplayed: 10uF  [0603L]  (hidden comment: GRM188Z71A106MA73D)
R127  ValueDisplayed: 1.00k  [0201L]  (hidden comment: RC0201FR-071KL)
R128  ValueDisplayed: 499  [0201L]  (hidden comment: RC0201FR-07499RL)
R129  ValueDisplayed: 2.0  [0201L]  (hidden comment: RC0201JR-072RL)
R130  ValueDisplayed: 0  [0201L]  (hidden comment: CRCW02010000Z0ED)
R131  ValueDisplayed: 9.76k  [0201L]  (hidden comment: RC0201FR-079K76L)
R132  ValueDisplayed: 14.3k  [0201L]  (hidden comment: RC0201FR-0714K3L)
U15  OPA837IDBVR  [DBV0006A_N]
U16  REF3318AIDCKR  [DCK0003A_N]

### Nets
+3.3V: C104.1 C106.1 C107.1 U15.5(PD) U15.6(V+) U16.1(IN)
GND: C104.2 C106.2 C107.2 C108.2 R127.1 R132.1 U15.2(V-) U16.3(GND)
VREF: R130.2
NetC105_1: C105.1 R129.1 U15.1(OUT)
NetC105_2: C105.2 R127.2 R128.1 U15.4(IN-)
NetC108_1: C108.1 R131.2 R132.2 U15.3(IN+)
NetR128_2: R128.2 R129.2 R130.1
NetR131_1: R131.1 U16.2(OUT)

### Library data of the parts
C104 C107 = CMP-0064970-1: as C120 on sheet DC134_USB
C105 = CMP-0009762-1: CAP, CERM, 100 pF, 25 V, +/- 5%, C0G/NP0, 0201; Manufacturer: MuRata; TaMin_C: -55°C; Polarized: N; SizeAreaWB_mm2: 2.08; Value1: Unknown; U/M: EA; Value: 100pF; TaMax_C: 125°C; SizeZ_mm: 0.33; SizeX_mm: 0.6; SizeY_mm: 0.3; Cap_Case: 0201; Value2: 25V; SizeArea_mm2: 0.18; CompType: Capacitor; AEC Category: Q200
C106 C108 = CMP-0007497-5: CAP, CERM, 10 uF, 10 V, +/- 20%, X7R, 0603; Manufacturer: MuRata; TaMin_C: -55°C; Polarized: N; SizeAreaWB_mm2: 4.68; Value1: Unknown; U/M: EA; Value: 10uF; TaMax_C: 125°C; SizeZ_mm: 1; SizeX_mm: 1.6; SizeY_mm: 0.8; Cap_Case: 0603; SizeArea_mm2: 1.28; Cap_F: 10µF; AEC Category: Q200
R127 = CMP-0027453-1: RES, 1.00 k, 1%, 0.05 W, 0201; Manufacturer: Yageo America; Power_W: 50mW; TempCo: 200 ppm/C; Value_Code: 1k00; U/M: EA; Value: 1.00k; EIA_Code: E96; Res_ohm: 1k; SizeX_mm: 0.6; SizeY_mm: 0.3; SizeZ_mm: 0.26; Value2: 0.05W; SizeArea_mm2: 0.18; AEC Qualified: N; VDC_V: 25V; AEC Category: Q200
R128 = CMP-0027731-1: RES, 499, 1%, 0.05 W, 0201; Manufacturer: Yageo America; Power_W: 50mW; TempCo: 200 ppm/C; Value_Code: 499R; U/M: EA; Value: 499; EIA_Code: E96; SizeX_mm: 0.6; SizeY_mm: 0.3; SizeZ_mm: 0.26; Value2: 0.05W; SizeArea_mm2: 0.18; CompType: Resistor; AEC Qualified: N; VDC_V: 25V; AEC Category: Q200
R129 = CMP-0027094-3: RES, 2.0, 5%, 0.05 W, 0201; Manufacturer: Yageo America; Power_W: 50mW; TempCo: 350 ppm/C; Value_Code: 2R00; U/M: EA; Value: 2.0; EIA_Code: E24; Res_ohm: 2; SizeX_mm: 0.6; SizeY_mm: 0.3; SizeZ_mm: 0.26; Value2: 0.05W; SizeArea_mm2: 0.18; CompType: Resistor; AEC Qualified: N; VDC_V: 25V; AEC Category: Q200
R130 = CMP-0027008-4: as R133-R137 on sheet DC134_USB
R131 = CMP-0027940-1: RES, 9.76 k, 1%, 0.05 W, 0201; Manufacturer: Yageo America; Power_W: 50mW; TempCo: 200 ppm/C; Value_Code: 9k76; U/M: EA; Value: 9.76k; EIA_Code: E96; SizeX_mm: 0.6; SizeY_mm: 0.3; SizeZ_mm: 0.26; Value2: 0.05W; SizeArea_mm2: 0.18; CompType: Resistor; AEC Qualified: N; VDC_V: 25V; AEC Category: Q200
R132 = CMP-0027360-2: RES, 14.3 k, 1%, 0.05 W, 0201; Manufacturer: Yageo America; Power_W: 50mW; TempCo: 200 ppm/C; Value_Code: 14k3; U/M: EA; Value: 14.3k; EIA_Code: E96; SizeX_mm: 0.6; SizeY_mm: 0.3; SizeZ_mm: 0.26; Value2: 0.05W; SizeArea_mm2: 0.18; CompType: Resistor; AEC Qualified: N; VDC_V: 25V; AEC Category: Q200
U15 = CMP-0013237-2: Low Power, Precision, 105MHz, Voltage Feedback Op Amp, DBV0006A (SOT-6); Manufacturer: Texas Instruments; Alternate PartNumber: OPA837IDBVT; SizeX_mm: 2.8; SizeY_mm: 2.9; CompType: IC; SizeZ_mm: 1.45; SizeArea_mm2: 8.12; SizeAreaWB_mm2: 14.82; U/M: EA
U16 = CMP-0032542-1: 30 ppm / degC Drift, 3.9 uA Voltage Reference, -40 to 125 degC, 3-pin SC70 (DCK), Green (RoHS & no Sb/Br); Manufacturer: Texas Instruments; Temp Coeff(Max)(ppm/ degree C): 30; Iout/Iz(Max)(mA): 5; VI(Min)(V): 1.98; SubFamily: Series Voltage Reference; VO(V): 1.8; Rating: Catalog; Temp Coeff(Typ)(ppm/ degree C): 8; VI(Max)(V): 5.5

## Sheet DC134_FMC.SchDoc
size 431 x 279 mm; Date: Not shown in title block; ApprovedBy: Not shown in title block; CheckedBy: Not shown in title block; Author: Not shown in title block; CompanyName: Not shown in title block; Engineer: Not shown in title block; Organization: Not shown in title block; Address1: Not shown in title block; Address2: Not shown in title block; Address3: Not shown in title block; Address4: Not shown in title block; DocumentNumber: 8; Revision: Use project parameter SCH_Rev; SheetNumber: 8; SheetTotal: 9; PageSetup: Record=PageOptions¦CenterHorizontal=True¦CenterVertical=True¦PrintScale=1.00¦XCorrection=1.00¦YCorrection=1.00¦PrintKind=0¦BorderSize=5000000¦LeftOffset=0¦BottomOffset=0¦Orientation=2¦PaperLength=1000¦PaperWidth=1000¦Scale=100¦PaperSource=15¦PrintQuality=600¦MediaType=1¦DitherType=10¦PaperKind=Letter¦PrintScaleMode=1

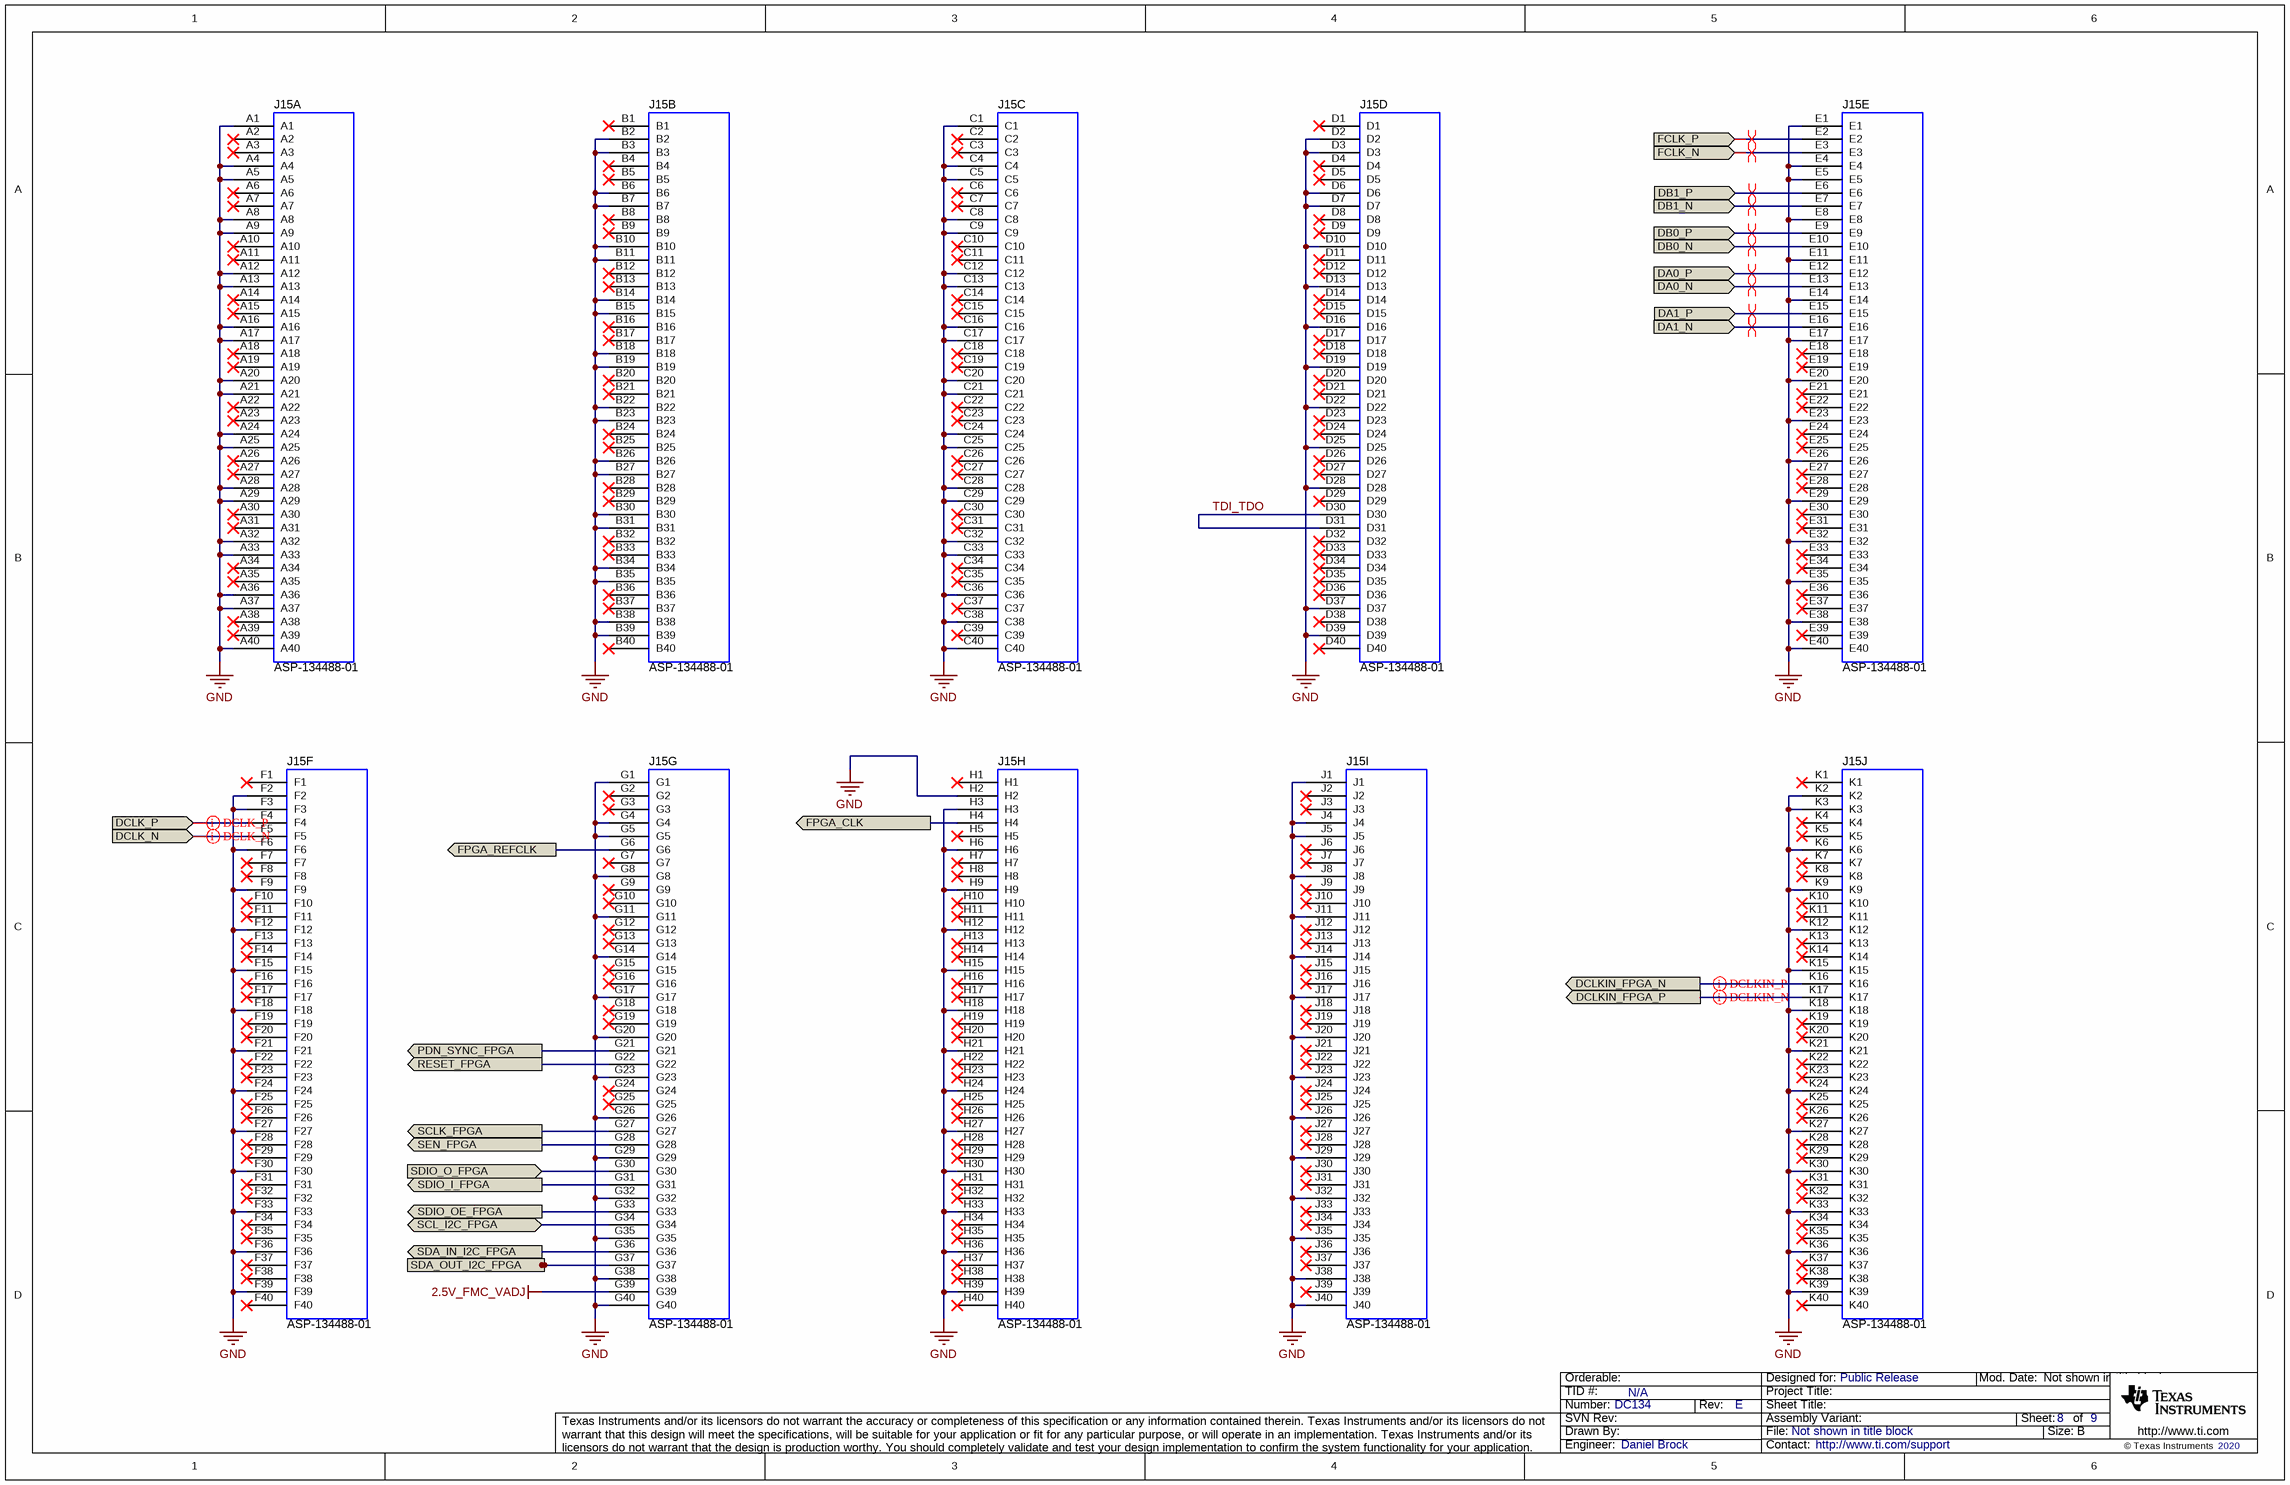
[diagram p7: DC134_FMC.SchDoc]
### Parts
J15  ASP-134488-01  [Samtec_ASP-134488-01]  (parts A,B,C,D,E,F,G,H,I,J of 10)

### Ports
DA0_N (in), DA0_P (in), DA1_N (in), DA1_P (in), DB0_N (in), DB0_P (in), DB1_N (in), DB1_P (in), DCLK_N (in), DCLK_P (in), DCLKIN_FPGA_N (out), DCLKIN_FPGA_P (out), FCLK_N (in), FCLK_P (in), FPGA_CLK (out), FPGA_REFCLK (out), PDN_SYNC_FPGA (out), RESET_FPGA (out), SCL_I2C_FPGA (bidir), SCLK_FPGA (out), SDA_IN_I2C_FPGA (out), SDA_OUT_I2C_FPGA (in), SDIO_I_FPGA (out), SDIO_O_FPGA (in), SDIO_OE_FPGA (out), SEN_FPGA (out)

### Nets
2.5V_FMC_VADJ: J15.G39
GND: J15.A1 J15.A4 J15.A5 J15.A8 J15.A9 J15.A12 J15.A13 J15.A16 J15.A17 J15.A20 J15.A21 J15.A24 J15.A25 J15.A28 J15.A29 J15.A32 J15.A33 J15.A36 J15.A37 J15.A40 J15.B2 J15.B3 J15.B6 J15.B7 J15.B10 J15.B11 J15.B14 J15.B15 J15.B18 J15.B19 J15.B22 J15.B23 J15.B26 J15.B27 J15.B30 J15.B31 J15.B34 J15.B35 J15.B38 J15.B39 J15.C1 J15.C4 J15.C5 J15.C8 J15.C9 J15.C12 J15.C13 J15.C16 J15.C17 J15.C20 J15.C21 J15.C24 J15.C25 J15.C28 J15.C29 J15.C32 J15.C33 J15.C36 J15.C38 J15.C40 J15.D2 J15.D3 J15.D6 J15.D7 J15.D10 J15.D13 J15.D16 J15.D19 J15.D22 J15.D25 J15.D28 J15.D37 J15.D39 J15.E1 J15.E4 J15.E5 J15.E8 J15.E11 J15.E14 J15.E17 J15.E20 J15.E23 J15.E26 J15.E29 J15.E32 J15.E35 J15.E38 J15.E40 J15.F2 J15.F3 J15.F6 J15.F9 J15.F12 J15.F15 J15.F18 J15.F21 J15.F24 J15.F27 J15.F30 J15.F33 J15.F36 J15.F39 J15.G1 J15.G4 J15.G5 J15.G8 J15.G11 J15.G14 J15.G17 J15.G20 J15.G23 J15.G26 J15.G29 J15.G32 J15.G35 J15.G38 J15.G40 J15.H2 J15.H3 J15.H6 J15.H9 J15.H12 J15.H15 J15.H18 J15.H21 J15.H24 J15.H27 J15.H30 J15.H33 J15.H36 J15.H39 J15.J1 J15.J4 J15.J5 J15.J8 J15.J11 J15.J14 J15.J17 J15.J20 J15.J23 J15.J26 J15.J29 J15.J32 J15.J35 J15.J38 J15.J40 J15.K2 J15.K3 J15.K6 J15.K9 J15.K12 J15.K15 J15.K18 J15.K21 J15.K24 J15.K27 J15.K30 J15.K33 J15.K36 J15.K39
DA0_N: J15.E13 ; port DA0_N
DA0_P: J15.E12 ; port DA0_P
DA1_N: J15.E16 ; port DA1_N
DA1_P: J15.E15 ; port DA1_P
DB0_N: J15.E10 ; port DB0_N
DB0_P: J15.E9 ; port DB0_P
DB1_N: J15.E7 ; port DB1_N
DB1_P: J15.E6 ; port DB1_P
DCLK_N: J15.F5 ; port DCLK_N
DCLK_P: J15.F4 ; port DCLK_P
DCLKIN_FPGA_N: J15.K16 ; port DCLKIN_FPGA_N
DCLKIN_FPGA_P: J15.K17 ; port DCLKIN_FPGA_P
FCLK_N: J15.E3 ; port FCLK_N
FCLK_P: J15.E2 ; port FCLK_P
FPGA_CLK: J15.H4 ; port FPGA_CLK
FPGA_REFCLK: J15.G6 ; port FPGA_REFCLK
PDN_SYNC_FPGA: J15.G21 ; port PDN_SYNC_FPGA
RESET_FPGA: J15.G22 ; port RESET_FPGA
SCL_I2C_FPGA: J15.G34 ; port SCL_I2C_FPGA
SCLK_FPGA: J15.G27 ; port SCLK_FPGA
SDA_IN_I2C_FPGA: J15.G36 ; port SDA_IN_I2C_FPGA
SDA_OUT_I2C_FPGA: J15.G37 ; port SDA_OUT_I2C_FPGA
SDIO_I_FPGA: J15.G31 ; port SDIO_I_FPGA
SDIO_O_FPGA: J15.G30 ; port SDIO_O_FPGA
SDIO_OE_FPGA: J15.G33 ; port SDIO_OE_FPGA
SEN_FPGA: J15.G28 ; port SEN_FPGA
TDI_TDO: J15.D30 J15.D31

Not connected (* = marked no-connect by the designer): J15 A2* A3* A6* A7* A10* A11* A14* A15* A18* A19* A22* A23* A26* A27* A30* A31* A34* A35* A38* A39* B1* B4* B5* B8* B9* B12* B13* B16* B17* B20* B21* B24* B25* B28* B29* B32* B33* B36* B37* B40* C2* C3* C6* C7* C10* C11* C14* C15* C18* C19* C22* C23* C26* C27* C30* C31* C34* C35* C37* C39* D1* D4* D5* D8* D9* D11* D12* D14* D15* D17* D18* D20* D21* D23* D24* D26* D27* D29* D32* D33* D34* D35* D36* D38* D40* E18* E19* E21* E22* E24* E25* E27* E28* E30* E31* E33* E34* E36* E37* E39* F1* F7* F8* F10* F11* F13* F14* F16* F17* F19* F20* F22* F23* F25* F26* F28* F29* F31* F32* F34* F35* F37* F38* F40* G2* G3* G7* G9* G10* G12* G13* G15* G16* G18* G19* G24* G25* H1* H5* H7* H8* H10* H11* H13* H14* H16* H17* H19* H20* H22* H23* H25* H26* H28* H29* H31* H32* H34* H35* H37* H38* H40* J2* J3* J6* J7* J9* J10* J12* J13* J15* J16* J18* J19* J21* J22* J24* J25* J27* J28* J30* J31* J33* J34* J36* J37* J39* K1* K4* K5* K7* K8* K10* K11* K13* K14* K19* K20* K22* K23* K25* K26* K28* K29* K31* K32* K34* K35* K37* K38* K40*

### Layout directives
differential pair: DA0_N, DA0_P, DA1_N, DA1_P, DB0_N, DB0_P, DB1_N, DB1_P, DCLK_N, DCLK_P, DCLKIN_FPGA_N, DCLKIN_FPGA_P, FCLK_N, FCLK_P

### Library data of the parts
J15 = CMP-0075635-1: Connector, 1.27mm, 40x10, Black, SMT; Manufacturer: Samtec; Pitch_mm: 1.27; Gender: Male; Cert_UL: Y; Green_REACh: Incomplete; CT: True; Green_Lifecycle: Not Set; Row_Count: 10; CompType: Terminal Block; CNHeader: False

## Sheet DC134_Hardware.SchDoc
size 431 x 279 mm; Date: Not shown in title block; ApprovedBy: Not shown in title block; CheckedBy: Not shown in title block; Author: Not shown in title block; CompanyName: Not shown in title block; Engineer: Not shown in title block; Organization: Not shown in title block; Address1: Not shown in title block; Address2: Not shown in title block; Address3: Not shown in title block; Address4: Not shown in title block; DocumentNumber: 9; Revision: Use project parameter SCH_Rev; SheetNumber: 9; SheetTotal: 9; PageSetup: Record=PageOptions¦CenterHorizontal=True¦CenterVertical=True¦PrintScale=1.00¦XCorrection=1.00¦YCorrection=1.00¦PrintKind=0¦BorderSize=5000000¦LeftOffset=0¦BottomOffset=0¦Orientation=2¦PaperLength=1000¦PaperWidth=1000¦Scale=100¦PaperSource=15¦PrintQuality=600¦MediaType=1¦DitherType=10¦PaperKind=Letter¦PrintScaleMode=1

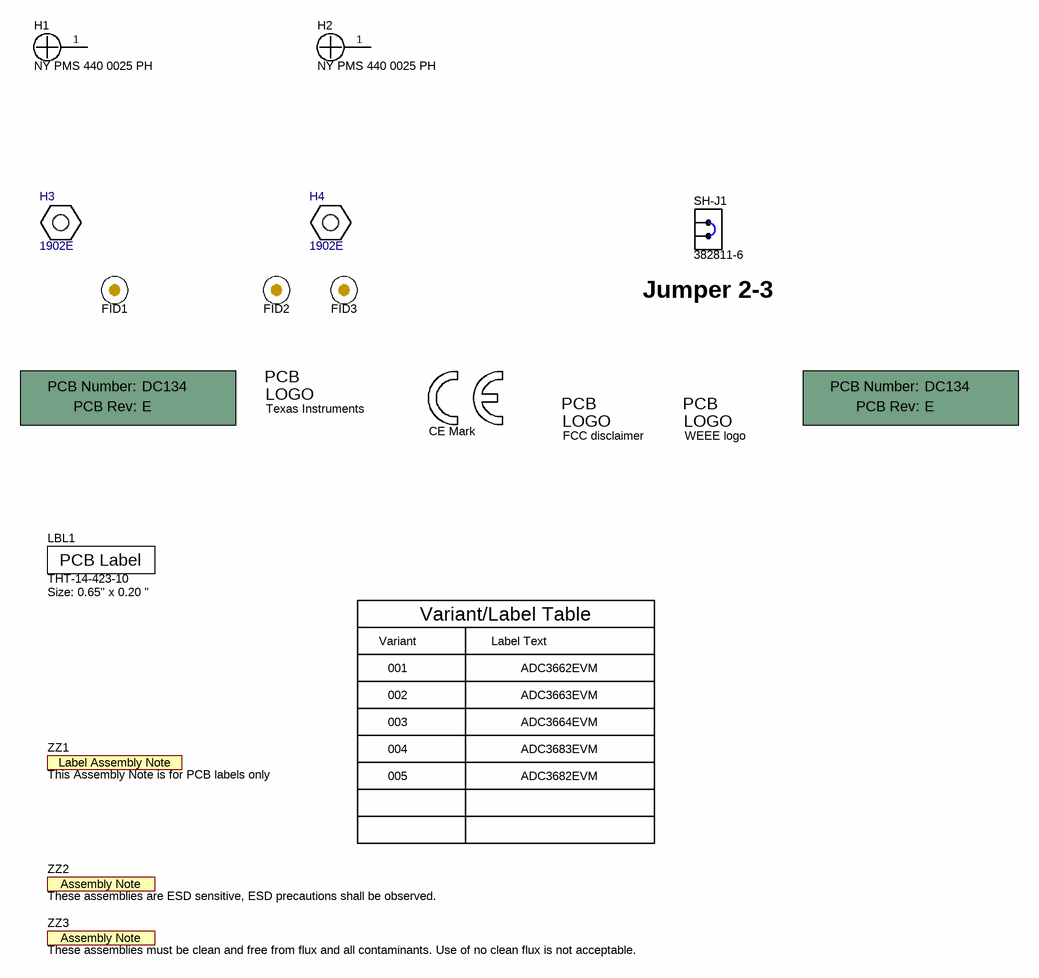
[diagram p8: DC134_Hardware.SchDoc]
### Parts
!PCB1  Printed Circuit Board  (value not drawn)  (mechanical)
!PCB2  Printed Circuit Board  (value not drawn)  (mechanical)
FID1  Fiducial  [Fiducial10-20]  (value not drawn)
FID2  Fiducial  [Fiducial10-20]  (value not drawn)
FID3  Fiducial  [Fiducial10-20]  (value not drawn)
H1  NY PMS 440 0025 PH  [NY PMS 440 0025 PH]
H2  NY PMS 440 0025 PH  [NY PMS 440 0025 PH]
H3  1902E  [Keystone_1902E]
H4  1902E  [Keystone_1902E]
LBL1  THT-14-423-10  Note: Size: 0.65" x 0.20 "  [Label_650x200]
Logo1  Texas Instruments  [TI_Stacked_Overlay_Small]  (no BOM)
Logo2  CE Mark  [CE_Mark_5mm]  (no BOM)
Logo3  FCC disclaimer  [FCC_disclaimer]  (no BOM)
Logo4  WEEE logo  [WEEE_Minimum]  (no BOM)
SH-J1  382811-6  (mechanical)
ZZ1  This Assembly Note is for PCB labels only  [AssemblyNoteLabel]  (no BOM)
ZZ2  These assemblies are ESD sensitive, ESD precautions shall be observed.  [AssemblyNote]  (no BOM)
ZZ3  These assemblies must be clean and free from flux and all contaminants. Use of no clean flux is not acceptable.  [AssemblyNote]  (no BOM)

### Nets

Not connected (* = marked no-connect by the designer): H1 1; H2 1

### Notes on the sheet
- (near SH-J1) Jumper 2-3
- Variant
- Variant/Label Table
- Label Text
- 001
- 002
- ADC3662EVM
- ADC3663EVM
- 003
- 004
- 005
- ADC3664EVM
- ADC3683EVM
- ADC3682EVM

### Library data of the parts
!PCB1 = CMP-0003618-2: Manufacturer: Any; PartNumber: DC134; CompType: PCB
!PCB2 = CMP-0003618-2: Printed Circuit Board, LVDS Interposer Card 35XX_L_INT; Manufacturer: Any; PartNumber: DC134; CompType: PCB
FID1-FID3 = CMP-0077181-1: Fiducial mark.  There is nothing to buy or mount.
H1 H2 = CMP-0003617-1: Machine Screw, Round, #4-40 x 1/4, Nylon, Philips panhead; Manufacturer: B&F Fastener Supply; CompType: Hardware
H3 H4 = CMP-0003611-1: Manufacturer: Keystone; CompType: Hardware
LBL1 = CMP-0003625-1: Thermal Transfer Printable Labels, 0.650" W x 0.200" H - 10,000 per roll; Manufacturer: Brady; CompType: Label
Logo1 = CMP-0074838-1: Texas Instrument Corporate Signature; SymbolCreator: a0412235; Lib Reference: TI_Logo; Library Reference: Logo
Logo2 = CMP-0074844-1: SymbolCreator: a0412235
Logo3 = CMP-0074847-1: FCC_disclaimer; Library Reference: Logo
Logo4 = CMP-0074769-1
SH-J1 = CMP-0003613-1: Shunt, 100mil, Gold plated, Black; Manufacturer: AMP; Value: 1x2
ZZ1 = CMP-0003616-3
ZZ2 = CMP-0077236-1
ZZ3 = CMP-0077237-1

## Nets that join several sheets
2.5V_FMC_VADJ: DC134_USB (5 pins), DC134_FMC (J15.G39)
+3.3V: DC134_FDA (R83.2 R91.2 R100.2 R106.2), DC134_CLK (15 pins), DC134_USB (25 pins), DC134_Power (12 pins), DC134_Reference (6 pins)
-0.23V_CHA: DC134_FDA (8 pins), DC134_Power (C95.1 R123.2)
-0.23V_CHB: DC134_FDA (8 pins), DC134_Power (C97.1 R124.2)
AVDD: DC134_Device (12 pins), DC134_CLK (R31.2 Y1.4), DC134_Power (5 pins)
GND: DC134_Device (27 pins), DC134_AIN (30 pins), DC134_FDA (24 pins), DC134_CLK (61 pins), DC134_USB (41 pins), DC134_Power (54 pins), DC134_Reference (8 pins), DC134_FMC (160 pins)
IOVDD: DC134_Device (6 pins), DC134_USB (C121.1 U18.1), DC134_Power (5 pins)
USB_+5Vin: DC134_USB (J17.1), DC134_Power (J16.3)
VCM_FDA_CHA: DC134_Device (R74.2), DC134_AIN (C5.2 R7.1 R8.2), DC134_FDA (C51.2 U6.9)
VCM_FDA_CHB: DC134_Device (R75.2), DC134_AIN (C13.2 R21.1 R22.2), DC134_FDA (C56.2 U7.9)
VREF: DC134_Device (C44.1 C45.1 R77.2 U4.2), DC134_Reference (R130.2)
AIN_N: DC134_Device (U4.13), DC134_AIN (R5.2)
AIN_P: DC134_Device (U4.12), DC134_AIN (R12.2)
AMP_CHA_IN_N: DC134_AIN (R13.1), DC134_FDA (R86.1 R89.2 R90.2)
AMP_CHA_IN_P: DC134_AIN (R2.1), DC134_FDA (R80.1 R81.1 R84.1)
AMP_CHA_OUT_N: DC134_AIN (R14.1), DC134_FDA (C53.2 L12.2 R85.1)
AMP_CHA_OUT_P: DC134_AIN (R1.1), DC134_FDA (C53.1 L11.2 R85.2)
AMP_CHB_IN_N: DC134_AIN (R27.1), DC134_FDA (R103.1 R107.2 R108.2)
AMP_CHB_IN_P: DC134_AIN (R16.1), DC134_FDA (R97.1 R98.1 R101.1)
AMP_CHB_OUT_N: DC134_AIN (R28.1), DC134_FDA (C58.2 L14.2 R102.1)
AMP_CHB_OUT_P: DC134_AIN (R15.1), DC134_FDA (C58.1 L13.2 R102.2)
BIN_N: DC134_Device (U4.38), DC134_AIN (R26.2)
BIN_P: DC134_Device (U4.39), DC134_AIN (R19.2)
CLK_N: DC134_Device (U4.7), DC134_CLK (C26.2 R52.2)
CLK_P: DC134_Device (U4.6), DC134_CLK (C21.2 R30.2 R39.2 R44.2)
DA0_N: DC134_Device (U4.19), DC134_FMC (J15.E13)
DA0_P: DC134_Device (U4.20), DC134_FMC (J15.E12)
DA1_N: DC134_Device (U4.17), DC134_FMC (J15.E16)
DA1_P: DC134_Device (U4.18), DC134_FMC (J15.E15)
DB0_N: DC134_Device (U4.32), DC134_FMC (J15.E10)
DB0_P: DC134_Device (U4.31), DC134_FMC (J15.E9)
DB1_N: DC134_Device (U4.34), DC134_FMC (J15.E7)
DB1_P: DC134_Device (U4.33), DC134_FMC (J15.E6)
DCLK_N: DC134_Device (U4.22), DC134_FMC (J15.F5)
DCLK_P: DC134_Device (U4.23), DC134_FMC (J15.F4)
DCLKIN_FPGA_N: DC134_CLK (U2.9), DC134_FMC (J15.K16)
DCLKIN_FPGA_P: DC134_CLK (U2.10), DC134_FMC (J15.K17)
DCLKIN_N: DC134_Device (U4.24), DC134_CLK (U2.3)
DCLKIN_P: DC134_Device (U4.25), DC134_CLK (U2.2)
FCLK_N: DC134_Device (U4.29), DC134_FMC (J15.E3)
FCLK_P: DC134_Device (U4.28), DC134_FMC (J15.E2)
FPGA_CLK: DC134_CLK (R39.1), DC134_FMC (J15.H4)
FPGA_REFCLK: DC134_CLK (R29.2), DC134_FMC (J15.G6)
SCL_I2C: DC134_CLK (U3.12), DC134_USB (R154.1 R156.2 R166.2), DC134_Power (U8.5 U9.5)
SCL_I2C_FPGA: DC134_USB (R163.2 R165.1), DC134_FMC (J15.G34)
SCLK: DC134_Device (U4.35), DC134_USB (U18.5)
SCLK_FPGA: DC134_USB (R133.1), DC134_FMC (J15.G27)
SDA_I2C: DC134_CLK (U3.19), DC134_USB (R155.1 R161.2 U20.4 U23.2), DC134_Power (U8.4 U9.4)
SDA_IN_I2C_FPGA: DC134_USB (R168.1), DC134_FMC (J15.G36)
SDA_OUT_I2C_FPGA: DC134_USB (R164.2 R167.1), DC134_FMC (J15.G37)
SDIO: DC134_Device (U4.10), DC134_USB (U18.3)
SDIO_I_FPGA: DC134_USB (R136.1), DC134_FMC (J15.G31)
SDIO_O_FPGA: DC134_USB (R137.1), DC134_FMC (J15.G30)
SDIO_OE_FPGA: DC134_USB (R135.1), DC134_FMC (J15.G33)
SEN: DC134_Device (U4.16), DC134_USB (U18.4)
SEN_FPGA: DC134_USB (R134.1), DC134_FMC (J15.G28)

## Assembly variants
001: not fitted C1 C8 C9 C16 C25 C30 C50 C53 C54 C55 C58 C59 FID1 FID2 FID3 J8 J10 L2 L5 L7 L16 R1 R2 R13 R14 R15 R16 R27 R28 R29 R30 R31 R32 R33 R38 R39 R41 R43 R44 R49 R50 R51 R52 R54 R57 R60 R61 R62 R63 R64 R65 R66 R67 R68 R69 R70 R71 R72 R85 R87 R93 R102 R104 R110 R121 R122 R133 R134 R135 R136 R137 R143 R146 R149 R151 R165 R166 R167 R168 Y1 Y3; alternate parts U4 -> CMP-0090117-2
002: not fitted C1 C8 C9 C16 C25 C30 C50 C53 C54 C55 C58 C59 FID1 FID2 FID3 J8 J10 L2 L5 L7 L16 R1 R2 R13 R14 R15 R16 R27 R28 R29 R30 R31 R32 R33 R38 R39 R41 R43 R44 R49 R50 R51 R52 R54 R57 R60 R61 R62 R63 R64 R65 R66 R67 R68 R69 R70 R71 R72 R85 R87 R93 R102 R104 R110 R121 R122 R133 R134 R135 R136 R137 R143 R146 R149 R151 R165 R166 R167 R168 Y1 Y3; alternate parts U4 -> CMP-0090118-2
003: not fitted C1 C8 C9 C16 C25 C30 C50 C53 C54 C55 C58 C59 FID1 FID2 FID3 J8 J10 L2 L5 L7 L16 R1 R2 R13 R14 R15 R16 R27 R28 R29 R30 R31 R32 R33 R38 R39 R41 R43 R44 R49 R50 R51 R52 R54 R57 R60 R61 R62 R63 R64 R65 R66 R67 R68 R69 R70 R71 R72 R85 R87 R93 R102 R104 R110 R121 R122 R133 R134 R135 R136 R137 R143 R146 R149 R151 R165 R166 R167 R168 Y1 Y3; alternate parts U4 -> CMP-0090119-2, R3 -> CMP-0058651-1, R10 -> CMP-0058651-1, R17 -> CMP-0058651-1, R24 -> CMP-0058651-1
004: not fitted C1 C8 C9 C16 C25 C30 C50 C53 C54 C55 C58 C59 FID1 FID2 FID3 J8 J10 L2 L5 L7 L16 R1 R2 R13 R14 R15 R16 R27 R28 R29 R30 R31 R32 R33 R38 R39 R41 R43 R44 R49 R50 R51 R52 R54 R57 R60 R61 R62 R63 R64 R65 R66 R67 R68 R69 R70 R71 R72 R85 R87 R93 R102 R104 R110 R121 R122 R133 R134 R135 R136 R137 R143 R146 R149 R151 R165 R166 R167 R168 Y1 Y3
005: not fitted C1 C8 C9 C16 C25 C30 C50 C53 C54 C55 C58 C59 FID1 FID2 FID3 J8 J10 L2 L5 L7 L16 R1 R2 R13 R14 R15 R16 R27 R28 R29 R30 R31 R32 R33 R38 R39 R41 R43 R44 R49 R50 R51 R52 R54 R57 R60 R61 R62 R63 R64 R65 R66 R67 R68 R69 R70 R71 R72 R85 R87 R93 R102 R104 R110 R121 R122 R133 R134 R135 R136 R137 R143 R146 R149 R151 R165 R166 R167 R168 Y1 Y3; alternate parts U4 -> CMP-0090120-2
